VERSION 5.8 ;
BUSBITCHARS "[]" ;
DIVIDERCHAR "/" ;
UNITS
    DATABASE MICRONS 1000 ;
END UNITS

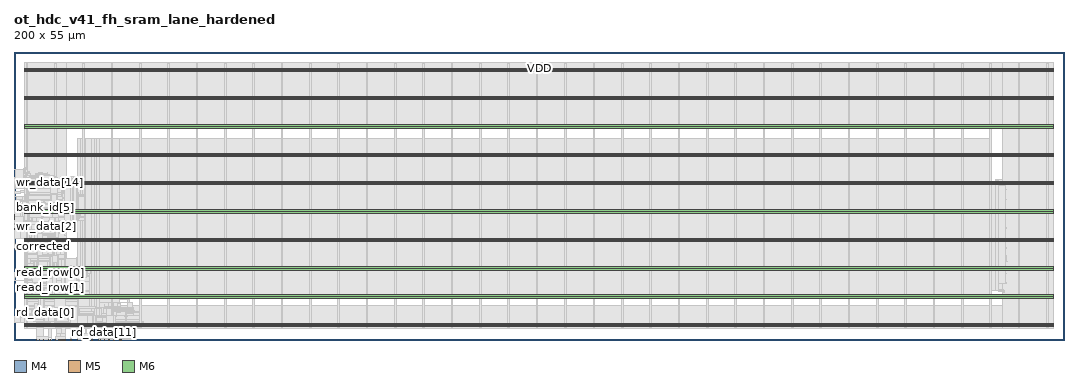
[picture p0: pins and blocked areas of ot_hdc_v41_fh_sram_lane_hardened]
MACRO ot_hdc_v41_fh_sram_lane_hardened
  FOREIGN ot_hdc_v41_fh_sram_lane_hardened 0 0 ;
  CLASS BLOCK ;
  SIZE 200 BY 55 ;
  PIN bank_id[0]
    DIRECTION INPUT ;
    USE SIGNAL ;
    PORT
      LAYER M4 ;
        RECT  0 26.4 0.084 26.424 ;
    END
  END bank_id[0]
  PIN bank_id[1]
    DIRECTION INPUT ;
    USE SIGNAL ;
    PORT
      LAYER M4 ;
        RECT  0 22.368 0.084 22.392 ;
    END
  END bank_id[1]
  PIN bank_id[2]
    DIRECTION INPUT ;
    USE SIGNAL ;
    PORT
      LAYER M4 ;
        RECT  0 22.176 0.084 22.2 ;
    END
  END bank_id[2]
  PIN bank_id[3]
    DIRECTION INPUT ;
    USE SIGNAL ;
    PORT
      LAYER M4 ;
        RECT  0 22.944 0.084 22.968 ;
    END
  END bank_id[3]
  PIN bank_id[4]
    DIRECTION INPUT ;
    USE SIGNAL ;
    PORT
      LAYER M4 ;
        RECT  0 23.616 0.084 23.64 ;
    END
  END bank_id[4]
  PIN bank_id[5]
    DIRECTION INPUT ;
    USE SIGNAL ;
    PORT
      LAYER M4 ;
        RECT  0 25.248 0.084 25.272 ;
    END
  END bank_id[5]
  PIN clk
    DIRECTION INPUT ;
    USE SIGNAL ;
    PORT
      LAYER M4 ;
        RECT  0 30.528 0.084 30.552 ;
    END
  END clk
  PIN corrected
    DIRECTION OUTPUT ;
    USE SIGNAL ;
    PORT
      LAYER M4 ;
        RECT  0 19.392 0.084 19.416 ;
    END
  END corrected
  PIN poisoned
    DIRECTION OUTPUT ;
    USE SIGNAL ;
    PORT
      LAYER M4 ;
        RECT  0 19.584 0.084 19.608 ;
    END
  END poisoned
  PIN rd_data[0]
    DIRECTION OUTPUT ;
    USE SIGNAL ;
    PORT
      LAYER M4 ;
        RECT  0 3.744 0.084 3.768 ;
    END
  END rd_data[0]
  PIN rd_data[10]
    DIRECTION OUTPUT ;
    USE SIGNAL ;
    PORT
      LAYER M5 ;
        RECT  4.8 0 4.824 0.084 ;
    END
  END rd_data[10]
  PIN rd_data[11]
    DIRECTION OUTPUT ;
    USE SIGNAL ;
    PORT
      LAYER M5 ;
        RECT  17.184 0 17.208 0.084 ;
    END
  END rd_data[11]
  PIN rd_data[12]
    DIRECTION OUTPUT ;
    USE SIGNAL ;
    PORT
      LAYER M5 ;
        RECT  18.24 0 18.264 0.084 ;
    END
  END rd_data[12]
  PIN rd_data[13]
    DIRECTION OUTPUT ;
    USE SIGNAL ;
    PORT
      LAYER M5 ;
        RECT  17.952 0 17.976 0.084 ;
    END
  END rd_data[13]
  PIN rd_data[14]
    DIRECTION OUTPUT ;
    USE SIGNAL ;
    PORT
      LAYER M5 ;
        RECT  18.912 0 18.936 0.084 ;
    END
  END rd_data[14]
  PIN rd_data[15]
    DIRECTION OUTPUT ;
    USE SIGNAL ;
    PORT
      LAYER M5 ;
        RECT  20.256 0 20.28 0.084 ;
    END
  END rd_data[15]
  PIN rd_data[16]
    DIRECTION OUTPUT ;
    USE SIGNAL ;
    PORT
      LAYER M5 ;
        RECT  20.16 0 20.184 0.084 ;
    END
  END rd_data[16]
  PIN rd_data[17]
    DIRECTION OUTPUT ;
    USE SIGNAL ;
    PORT
      LAYER M5 ;
        RECT  20.352 0 20.376 0.084 ;
    END
  END rd_data[17]
  PIN rd_data[18]
    DIRECTION OUTPUT ;
    USE SIGNAL ;
    PORT
      LAYER M5 ;
        RECT  20.448 0 20.472 0.084 ;
    END
  END rd_data[18]
  PIN rd_data[19]
    DIRECTION OUTPUT ;
    USE SIGNAL ;
    PORT
      LAYER M5 ;
        RECT  20.064 0 20.088 0.084 ;
    END
  END rd_data[19]
  PIN rd_data[1]
    DIRECTION OUTPUT ;
    USE SIGNAL ;
    PORT
      LAYER M5 ;
        RECT  4.32 0 4.344 0.084 ;
    END
  END rd_data[1]
  PIN rd_data[20]
    DIRECTION OUTPUT ;
    USE SIGNAL ;
    PORT
      LAYER M5 ;
        RECT  19.104 0 19.128 0.084 ;
    END
  END rd_data[20]
  PIN rd_data[21]
    DIRECTION OUTPUT ;
    USE SIGNAL ;
    PORT
      LAYER M5 ;
        RECT  16.512 0 16.536 0.084 ;
    END
  END rd_data[21]
  PIN rd_data[22]
    DIRECTION OUTPUT ;
    USE SIGNAL ;
    PORT
      LAYER M5 ;
        RECT  16.032 0 16.056 0.084 ;
    END
  END rd_data[22]
  PIN rd_data[23]
    DIRECTION OUTPUT ;
    USE SIGNAL ;
    PORT
      LAYER M5 ;
        RECT  13.824 0 13.848 0.084 ;
    END
  END rd_data[23]
  PIN rd_data[24]
    DIRECTION OUTPUT ;
    USE SIGNAL ;
    PORT
      LAYER M5 ;
        RECT  12.864 0 12.888 0.084 ;
    END
  END rd_data[24]
  PIN rd_data[25]
    DIRECTION OUTPUT ;
    USE SIGNAL ;
    PORT
      LAYER M5 ;
        RECT  14.976 0 15 0.084 ;
    END
  END rd_data[25]
  PIN rd_data[26]
    DIRECTION OUTPUT ;
    USE SIGNAL ;
    PORT
      LAYER M5 ;
        RECT  12 0 12.024 0.084 ;
    END
  END rd_data[26]
  PIN rd_data[27]
    DIRECTION OUTPUT ;
    USE SIGNAL ;
    PORT
      LAYER M5 ;
        RECT  14.688 0 14.712 0.084 ;
    END
  END rd_data[27]
  PIN rd_data[28]
    DIRECTION OUTPUT ;
    USE SIGNAL ;
    PORT
      LAYER M5 ;
        RECT  13.152 0 13.176 0.084 ;
    END
  END rd_data[28]
  PIN rd_data[29]
    DIRECTION OUTPUT ;
    USE SIGNAL ;
    PORT
      LAYER M5 ;
        RECT  10.752 0 10.776 0.084 ;
    END
  END rd_data[29]
  PIN rd_data[2]
    DIRECTION OUTPUT ;
    USE SIGNAL ;
    PORT
      LAYER M4 ;
        RECT  0 3.264 0.084 3.288 ;
    END
  END rd_data[2]
  PIN rd_data[30]
    DIRECTION OUTPUT ;
    USE SIGNAL ;
    PORT
      LAYER M5 ;
        RECT  10.944 0 10.968 0.084 ;
    END
  END rd_data[30]
  PIN rd_data[31]
    DIRECTION OUTPUT ;
    USE SIGNAL ;
    PORT
      LAYER M4 ;
        RECT  0 4.416 0.084 4.44 ;
    END
  END rd_data[31]
  PIN rd_data[3]
    DIRECTION OUTPUT ;
    USE SIGNAL ;
    PORT
      LAYER M5 ;
        RECT  6.912 0 6.936 0.084 ;
    END
  END rd_data[3]
  PIN rd_data[4]
    DIRECTION OUTPUT ;
    USE SIGNAL ;
    PORT
      LAYER M5 ;
        RECT  8.544 0 8.568 0.084 ;
    END
  END rd_data[4]
  PIN rd_data[5]
    DIRECTION OUTPUT ;
    USE SIGNAL ;
    PORT
      LAYER M5 ;
        RECT  7.968 0 7.992 0.084 ;
    END
  END rd_data[5]
  PIN rd_data[6]
    DIRECTION OUTPUT ;
    USE SIGNAL ;
    PORT
      LAYER M5 ;
        RECT  9.696 0 9.72 0.084 ;
    END
  END rd_data[6]
  PIN rd_data[7]
    DIRECTION OUTPUT ;
    USE SIGNAL ;
    PORT
      LAYER M5 ;
        RECT  9.024 0 9.048 0.084 ;
    END
  END rd_data[7]
  PIN rd_data[8]
    DIRECTION OUTPUT ;
    USE SIGNAL ;
    PORT
      LAYER M5 ;
        RECT  5.664 0 5.688 0.084 ;
    END
  END rd_data[8]
  PIN rd_data[9]
    DIRECTION OUTPUT ;
    USE SIGNAL ;
    PORT
      LAYER M5 ;
        RECT  6.528 0 6.552 0.084 ;
    END
  END rd_data[9]
  PIN rd_valid
    DIRECTION OUTPUT ;
    USE SIGNAL ;
    PORT
      LAYER M4 ;
        RECT  0 19.872 0.084 19.896 ;
    END
  END rd_valid
  PIN read_ok
    DIRECTION INPUT ;
    USE SIGNAL ;
    PORT
      LAYER M5 ;
        RECT  8.736 0 8.76 0.084 ;
    END
  END read_ok
  PIN read_row[0]
    DIRECTION INPUT ;
    USE SIGNAL ;
    PORT
      LAYER M4 ;
        RECT  0 12.768 0.084 12.792 ;
    END
  END read_row[0]
  PIN read_row[1]
    DIRECTION INPUT ;
    USE SIGNAL ;
    PORT
      LAYER M4 ;
        RECT  0 11.52 0.084 11.544 ;
    END
  END read_row[1]
  PIN read_row[2]
    DIRECTION INPUT ;
    USE SIGNAL ;
    PORT
      LAYER M5 ;
        RECT  9.216 0 9.24 0.084 ;
    END
  END read_row[2]
  PIN read_row[3]
    DIRECTION INPUT ;
    USE SIGNAL ;
    PORT
      LAYER M5 ;
        RECT  9.312 0 9.336 0.084 ;
    END
  END read_row[3]
  PIN read_row[4]
    DIRECTION INPUT ;
    USE SIGNAL ;
    PORT
      LAYER M5 ;
        RECT  8.928 0 8.952 0.084 ;
    END
  END read_row[4]
  PIN read_row[5]
    DIRECTION INPUT ;
    USE SIGNAL ;
    PORT
      LAYER M5 ;
        RECT  8.64 0 8.664 0.084 ;
    END
  END read_row[5]
  PIN read_row[6]
    DIRECTION INPUT ;
    USE SIGNAL ;
    PORT
      LAYER M5 ;
        RECT  9.12 0 9.144 0.084 ;
    END
  END read_row[6]
  PIN read_row[7]
    DIRECTION INPUT ;
    USE SIGNAL ;
    PORT
      LAYER M5 ;
        RECT  9.408 0 9.432 0.084 ;
    END
  END read_row[7]
  PIN read_row[8]
    DIRECTION INPUT ;
    USE SIGNAL ;
    PORT
      LAYER M5 ;
        RECT  9.504 0 9.528 0.084 ;
    END
  END read_row[8]
  PIN rst_n
    DIRECTION INPUT ;
    USE SIGNAL ;
    PORT
      LAYER M4 ;
        RECT  0 19.68 0.084 19.704 ;
    END
  END rst_n
  PIN wr_committed
    DIRECTION OUTPUT ;
    USE SIGNAL ;
    PORT
      LAYER M4 ;
        RECT  0 19.968 0.084 19.992 ;
    END
  END wr_committed
  PIN wr_data[0]
    DIRECTION INPUT ;
    USE SIGNAL ;
    PORT
      LAYER M4 ;
        RECT  0 24.384 0.084 24.408 ;
    END
  END wr_data[0]
  PIN wr_data[10]
    DIRECTION INPUT ;
    USE SIGNAL ;
    PORT
      LAYER M4 ;
        RECT  0 20.928 0.084 20.952 ;
    END
  END wr_data[10]
  PIN wr_data[11]
    DIRECTION INPUT ;
    USE SIGNAL ;
    PORT
      LAYER M4 ;
        RECT  0 28.8 0.084 28.824 ;
    END
  END wr_data[11]
  PIN wr_data[12]
    DIRECTION INPUT ;
    USE SIGNAL ;
    PORT
      LAYER M4 ;
        RECT  0 23.04 0.084 23.064 ;
    END
  END wr_data[12]
  PIN wr_data[13]
    DIRECTION INPUT ;
    USE SIGNAL ;
    PORT
      LAYER M4 ;
        RECT  0 23.232 0.084 23.256 ;
    END
  END wr_data[13]
  PIN wr_data[14]
    DIRECTION INPUT ;
    USE SIGNAL ;
    PORT
      LAYER M4 ;
        RECT  0 29.952 0.084 29.976 ;
    END
  END wr_data[14]
  PIN wr_data[15]
    DIRECTION INPUT ;
    USE SIGNAL ;
    PORT
      LAYER M4 ;
        RECT  0 30.624 0.084 30.648 ;
    END
  END wr_data[15]
  PIN wr_data[16]
    DIRECTION INPUT ;
    USE SIGNAL ;
    PORT
      LAYER M4 ;
        RECT  0 30.816 0.084 30.84 ;
    END
  END wr_data[16]
  PIN wr_data[17]
    DIRECTION INPUT ;
    USE SIGNAL ;
    PORT
      LAYER M4 ;
        RECT  0 29.376 0.084 29.4 ;
    END
  END wr_data[17]
  PIN wr_data[18]
    DIRECTION INPUT ;
    USE SIGNAL ;
    PORT
      LAYER M4 ;
        RECT  0 30.912 0.084 30.936 ;
    END
  END wr_data[18]
  PIN wr_data[19]
    DIRECTION INPUT ;
    USE SIGNAL ;
    PORT
      LAYER M4 ;
        RECT  0 30.72 0.084 30.744 ;
    END
  END wr_data[19]
  PIN wr_data[1]
    DIRECTION INPUT ;
    USE SIGNAL ;
    PORT
      LAYER M4 ;
        RECT  0 20.832 0.084 20.856 ;
    END
  END wr_data[1]
  PIN wr_data[20]
    DIRECTION INPUT ;
    USE SIGNAL ;
    PORT
      LAYER M4 ;
        RECT  0 31.008 0.084 31.032 ;
    END
  END wr_data[20]
  PIN wr_data[21]
    DIRECTION INPUT ;
    USE SIGNAL ;
    PORT
      LAYER M4 ;
        RECT  0 29.856 0.084 29.88 ;
    END
  END wr_data[21]
  PIN wr_data[22]
    DIRECTION INPUT ;
    USE SIGNAL ;
    PORT
      LAYER M4 ;
        RECT  0 30.048 0.084 30.072 ;
    END
  END wr_data[22]
  PIN wr_data[23]
    DIRECTION INPUT ;
    USE SIGNAL ;
    PORT
      LAYER M4 ;
        RECT  0 29.76 0.084 29.784 ;
    END
  END wr_data[23]
  PIN wr_data[24]
    DIRECTION INPUT ;
    USE SIGNAL ;
    PORT
      LAYER M4 ;
        RECT  0 27.936 0.084 27.96 ;
    END
  END wr_data[24]
  PIN wr_data[25]
    DIRECTION INPUT ;
    USE SIGNAL ;
    PORT
      LAYER M4 ;
        RECT  0 26.208 0.084 26.232 ;
    END
  END wr_data[25]
  PIN wr_data[26]
    DIRECTION INPUT ;
    USE SIGNAL ;
    PORT
      LAYER M4 ;
        RECT  0 24.576 0.084 24.6 ;
    END
  END wr_data[26]
  PIN wr_data[27]
    DIRECTION INPUT ;
    USE SIGNAL ;
    PORT
      LAYER M4 ;
        RECT  0 29.472 0.084 29.496 ;
    END
  END wr_data[27]
  PIN wr_data[28]
    DIRECTION INPUT ;
    USE SIGNAL ;
    PORT
      LAYER M4 ;
        RECT  0 23.136 0.084 23.16 ;
    END
  END wr_data[28]
  PIN wr_data[29]
    DIRECTION INPUT ;
    USE SIGNAL ;
    PORT
      LAYER M4 ;
        RECT  0 24.768 0.084 24.792 ;
    END
  END wr_data[29]
  PIN wr_data[2]
    DIRECTION INPUT ;
    USE SIGNAL ;
    PORT
      LAYER M4 ;
        RECT  0 21.6 0.084 21.624 ;
    END
  END wr_data[2]
  PIN wr_data[30]
    DIRECTION INPUT ;
    USE SIGNAL ;
    PORT
      LAYER M4 ;
        RECT  0 26.592 0.084 26.616 ;
    END
  END wr_data[30]
  PIN wr_data[31]
    DIRECTION INPUT ;
    USE SIGNAL ;
    PORT
      LAYER M4 ;
        RECT  0 28.32 0.084 28.344 ;
    END
  END wr_data[31]
  PIN wr_data[3]
    DIRECTION INPUT ;
    USE SIGNAL ;
    PORT
      LAYER M4 ;
        RECT  0 23.808 0.084 23.832 ;
    END
  END wr_data[3]
  PIN wr_data[4]
    DIRECTION INPUT ;
    USE SIGNAL ;
    PORT
      LAYER M4 ;
        RECT  0 20.448 0.084 20.472 ;
    END
  END wr_data[4]
  PIN wr_data[5]
    DIRECTION INPUT ;
    USE SIGNAL ;
    PORT
      LAYER M4 ;
        RECT  0 20.16 0.084 20.184 ;
    END
  END wr_data[5]
  PIN wr_data[6]
    DIRECTION INPUT ;
    USE SIGNAL ;
    PORT
      LAYER M4 ;
        RECT  0 20.736 0.084 20.76 ;
    END
  END wr_data[6]
  PIN wr_data[7]
    DIRECTION INPUT ;
    USE SIGNAL ;
    PORT
      LAYER M4 ;
        RECT  0 20.256 0.084 20.28 ;
    END
  END wr_data[7]
  PIN wr_data[8]
    DIRECTION INPUT ;
    USE SIGNAL ;
    PORT
      LAYER M4 ;
        RECT  0 20.064 0.084 20.088 ;
    END
  END wr_data[8]
  PIN wr_data[9]
    DIRECTION INPUT ;
    USE SIGNAL ;
    PORT
      LAYER M4 ;
        RECT  0 20.544 0.084 20.568 ;
    END
  END wr_data[9]
  PIN write_ok
    DIRECTION INPUT ;
    USE SIGNAL ;
    PORT
      LAYER M4 ;
        RECT  0 19.776 0.084 19.8 ;
    END
  END write_ok
  PIN write_row[0]
    DIRECTION INPUT ;
    USE SIGNAL ;
    PORT
      LAYER M4 ;
        RECT  0 23.712 0.084 23.736 ;
    END
  END write_row[0]
  PIN write_row[1]
    DIRECTION INPUT ;
    USE SIGNAL ;
    PORT
      LAYER M4 ;
        RECT  0 24.192 0.084 24.216 ;
    END
  END write_row[1]
  PIN write_row[2]
    DIRECTION INPUT ;
    USE SIGNAL ;
    PORT
      LAYER M4 ;
        RECT  0 27.36 0.084 27.384 ;
    END
  END write_row[2]
  PIN write_row[3]
    DIRECTION INPUT ;
    USE SIGNAL ;
    PORT
      LAYER M4 ;
        RECT  0 21.12 0.084 21.144 ;
    END
  END write_row[3]
  PIN write_row[4]
    DIRECTION INPUT ;
    USE SIGNAL ;
    PORT
      LAYER M4 ;
        RECT  0 20.64 0.084 20.664 ;
    END
  END write_row[4]
  PIN write_row[5]
    DIRECTION INPUT ;
    USE SIGNAL ;
    PORT
      LAYER M4 ;
        RECT  0 22.08 0.084 22.104 ;
    END
  END write_row[5]
  PIN write_row[6]
    DIRECTION INPUT ;
    USE SIGNAL ;
    PORT
      LAYER M4 ;
        RECT  0 22.56 0.084 22.584 ;
    END
  END write_row[6]
  PIN write_row[7]
    DIRECTION INPUT ;
    USE SIGNAL ;
    PORT
      LAYER M4 ;
        RECT  0 25.824 0.084 25.848 ;
    END
  END write_row[7]
  PIN write_row[8]
    DIRECTION INPUT ;
    USE SIGNAL ;
    PORT
      LAYER M4 ;
        RECT  0 25.152 0.084 25.176 ;
    END
  END write_row[8]
  PIN VDD
    DIRECTION INOUT ;
    USE POWER ;
    PORT
      LAYER M6 ;
        RECT  2.052 51.513 197.964 51.801 ;
        RECT  2.052 46.113 197.964 46.401 ;
        RECT  2.052 40.713 197.964 41.001 ;
        RECT  2.052 35.313 197.964 35.601 ;
        RECT  2.052 29.913 197.964 30.201 ;
        RECT  2.052 24.513 197.964 24.801 ;
        RECT  2.052 19.113 197.964 19.401 ;
        RECT  2.052 13.713 197.964 14.001 ;
        RECT  2.052 8.313 197.964 8.601 ;
        RECT  2.052 2.913 197.964 3.201 ;
    END
  END VDD
  PIN VSS
    DIRECTION INOUT ;
    USE GROUND ;
    PORT
      LAYER M6 ;
        RECT  2.052 51.129 197.964 51.417 ;
        RECT  2.052 45.729 197.964 46.017 ;
        RECT  2.052 40.329 197.964 40.617 ;
        RECT  2.052 34.929 197.964 35.217 ;
        RECT  2.052 29.529 197.964 29.817 ;
        RECT  2.052 24.129 197.964 24.417 ;
        RECT  2.052 18.729 197.964 19.017 ;
        RECT  2.052 13.329 197.964 13.617 ;
        RECT  2.052 7.929 197.964 8.217 ;
        RECT  2.052 2.529 197.964 2.817 ;
    END
  END VSS
  OBS
    LAYER RVTN ;
     RECT  2.052 2.16 197.964 2.295 ;
     RECT  2.052 2.565 197.964 2.835 ;
     RECT  2.052 3.105 197.964 3.375 ;
     RECT  2.052 3.645 197.964 3.915 ;
     RECT  2.052 4.185 197.964 4.455 ;
     RECT  2.052 4.725 197.964 4.995 ;
     RECT  2.052 5.265 197.964 5.535 ;
     RECT  2.052 5.805 197.964 6.075 ;
     RECT  2.052 6.345 197.964 6.48 ;
     RECT  2.052 6.48 10.044 6.615 ;
     RECT  188.244 6.48 197.964 6.615 ;
     RECT  2.052 6.885 10.044 7.155 ;
     RECT  188.244 6.885 197.964 7.155 ;
     RECT  2.052 7.425 10.044 7.695 ;
     RECT  188.244 7.425 197.964 7.695 ;
     RECT  2.052 7.965 10.044 8.235 ;
     RECT  188.244 7.965 197.964 8.235 ;
     RECT  2.052 8.505 10.044 8.775 ;
     RECT  188.244 8.505 197.964 8.775 ;
     RECT  2.052 9.045 10.044 9.315 ;
     RECT  188.244 9.045 197.964 9.315 ;
     RECT  2.052 9.585 10.044 9.855 ;
     RECT  188.244 9.585 197.964 9.855 ;
     RECT  2.052 10.125 10.044 10.395 ;
     RECT  188.244 10.125 197.964 10.395 ;
     RECT  2.052 10.665 10.044 10.935 ;
     RECT  188.244 10.665 197.964 10.935 ;
     RECT  2.052 11.205 10.044 11.475 ;
     RECT  188.244 11.205 197.964 11.475 ;
     RECT  2.052 11.745 10.044 12.015 ;
     RECT  188.244 11.745 197.964 12.015 ;
     RECT  2.052 12.285 10.044 12.555 ;
     RECT  188.244 12.285 197.964 12.555 ;
     RECT  2.052 12.825 10.044 13.095 ;
     RECT  188.244 12.825 197.964 13.095 ;
     RECT  2.052 13.365 10.044 13.635 ;
     RECT  188.244 13.365 197.964 13.635 ;
     RECT  2.052 13.905 10.044 14.175 ;
     RECT  188.244 13.905 197.964 14.175 ;
     RECT  2.052 14.445 10.044 14.715 ;
     RECT  188.244 14.445 197.964 14.715 ;
     RECT  2.052 14.985 10.044 15.255 ;
     RECT  188.244 14.985 197.964 15.255 ;
     RECT  2.052 15.525 10.044 15.795 ;
     RECT  188.244 15.525 197.964 15.795 ;
     RECT  2.052 16.065 10.044 16.335 ;
     RECT  188.244 16.065 197.964 16.335 ;
     RECT  2.052 16.605 10.044 16.875 ;
     RECT  188.244 16.605 197.964 16.875 ;
     RECT  2.052 17.145 10.044 17.415 ;
     RECT  188.244 17.145 197.964 17.415 ;
     RECT  2.052 17.685 10.044 17.955 ;
     RECT  188.244 17.685 197.964 17.955 ;
     RECT  2.052 18.225 10.044 18.495 ;
     RECT  188.244 18.225 197.964 18.495 ;
     RECT  2.052 18.765 10.044 19.035 ;
     RECT  188.244 18.765 197.964 19.035 ;
     RECT  2.052 19.305 10.044 19.575 ;
     RECT  188.244 19.305 197.964 19.575 ;
     RECT  2.052 19.845 10.044 20.115 ;
     RECT  188.244 19.845 197.964 20.115 ;
     RECT  2.052 20.385 10.044 20.655 ;
     RECT  188.244 20.385 197.964 20.655 ;
     RECT  2.052 20.925 10.044 21.195 ;
     RECT  188.244 20.925 197.964 21.195 ;
     RECT  2.052 21.465 10.044 21.735 ;
     RECT  188.244 21.465 197.964 21.735 ;
     RECT  2.052 22.005 10.044 22.275 ;
     RECT  188.244 22.005 197.964 22.275 ;
     RECT  2.052 22.545 10.044 22.815 ;
     RECT  188.244 22.545 197.964 22.815 ;
     RECT  2.052 23.085 10.044 23.355 ;
     RECT  188.244 23.085 197.964 23.355 ;
     RECT  2.052 23.625 10.044 23.895 ;
     RECT  188.244 23.625 197.964 23.895 ;
     RECT  2.052 24.165 10.044 24.435 ;
     RECT  188.244 24.165 197.964 24.435 ;
     RECT  2.052 24.705 10.044 24.975 ;
     RECT  188.244 24.705 197.964 24.975 ;
     RECT  2.052 25.245 10.044 25.515 ;
     RECT  188.244 25.245 197.964 25.515 ;
     RECT  2.052 25.785 10.044 26.055 ;
     RECT  188.244 25.785 197.964 26.055 ;
     RECT  2.052 26.325 10.044 26.595 ;
     RECT  188.244 26.325 197.964 26.595 ;
     RECT  2.052 26.865 10.044 27.135 ;
     RECT  188.244 26.865 197.964 27.135 ;
     RECT  2.052 27.405 10.044 27.675 ;
     RECT  188.244 27.405 197.964 27.675 ;
     RECT  2.052 27.945 10.044 28.215 ;
     RECT  188.244 27.945 197.964 28.215 ;
     RECT  2.052 28.485 10.044 28.755 ;
     RECT  188.244 28.485 197.964 28.755 ;
     RECT  2.052 29.025 10.044 29.295 ;
     RECT  188.244 29.025 197.964 29.295 ;
     RECT  2.052 29.565 10.044 29.835 ;
     RECT  188.244 29.565 197.964 29.835 ;
     RECT  2.052 30.105 10.044 30.375 ;
     RECT  188.244 30.105 197.964 30.375 ;
     RECT  2.052 30.645 10.044 30.915 ;
     RECT  188.244 30.645 197.964 30.915 ;
     RECT  2.052 31.185 10.044 31.455 ;
     RECT  188.244 31.185 197.964 31.455 ;
     RECT  2.052 31.725 10.044 31.995 ;
     RECT  188.244 31.725 197.964 31.995 ;
     RECT  2.052 32.265 10.044 32.535 ;
     RECT  188.244 32.265 197.964 32.535 ;
     RECT  2.052 32.805 10.044 33.075 ;
     RECT  188.244 32.805 197.964 33.075 ;
     RECT  2.052 33.345 10.044 33.615 ;
     RECT  188.244 33.345 197.964 33.615 ;
     RECT  2.052 33.885 10.044 34.155 ;
     RECT  188.244 33.885 197.964 34.155 ;
     RECT  2.052 34.425 10.044 34.695 ;
     RECT  188.244 34.425 197.964 34.695 ;
     RECT  2.052 34.965 10.044 35.235 ;
     RECT  188.244 34.965 197.964 35.235 ;
     RECT  2.052 35.505 10.044 35.775 ;
     RECT  188.244 35.505 197.964 35.775 ;
     RECT  2.052 36.045 10.044 36.315 ;
     RECT  188.244 36.045 197.964 36.315 ;
     RECT  2.052 36.585 10.044 36.855 ;
     RECT  188.244 36.585 197.964 36.855 ;
     RECT  2.052 37.125 10.044 37.395 ;
     RECT  188.244 37.125 197.964 37.395 ;
     RECT  2.052 37.665 10.044 37.935 ;
     RECT  188.244 37.665 197.964 37.935 ;
     RECT  2.052 38.205 10.044 38.475 ;
     RECT  188.244 38.205 197.964 38.475 ;
     RECT  2.052 38.745 10.044 39.015 ;
     RECT  188.244 38.745 197.964 39.015 ;
     RECT  2.052 39.285 10.044 39.555 ;
     RECT  188.244 39.285 197.964 39.555 ;
     RECT  2.052 39.825 10.044 40.095 ;
     RECT  188.244 39.825 197.964 40.095 ;
     RECT  2.052 40.365 10.044 40.5 ;
     RECT  188.244 40.365 197.964 40.5 ;
     RECT  2.052 40.5 197.964 40.635 ;
     RECT  2.052 40.905 197.964 41.175 ;
     RECT  2.052 41.445 197.964 41.715 ;
     RECT  2.052 41.985 197.964 42.255 ;
     RECT  2.052 42.525 197.964 42.795 ;
     RECT  2.052 43.065 197.964 43.335 ;
     RECT  2.052 43.605 197.964 43.875 ;
     RECT  2.052 44.145 197.964 44.415 ;
     RECT  2.052 44.685 197.964 44.955 ;
     RECT  2.052 45.225 197.964 45.495 ;
     RECT  2.052 45.765 197.964 46.035 ;
     RECT  2.052 46.305 197.964 46.575 ;
     RECT  2.052 46.845 197.964 47.115 ;
     RECT  2.052 47.385 197.964 47.655 ;
     RECT  2.052 47.925 197.964 48.195 ;
     RECT  2.052 48.465 197.964 48.735 ;
     RECT  2.052 49.005 197.964 49.275 ;
     RECT  2.052 49.545 197.964 49.815 ;
     RECT  2.052 50.085 197.964 50.355 ;
     RECT  2.052 50.625 197.964 50.895 ;
     RECT  2.052 51.165 197.964 51.435 ;
     RECT  2.052 51.705 197.964 51.975 ;
     RECT  2.052 52.245 197.964 52.515 ;
     RECT  2.052 52.785 197.964 52.92 ;
    LAYER RVTP ;
     RECT  2.052 2.295 197.964 2.565 ;
     RECT  2.052 2.835 197.964 3.105 ;
     RECT  2.052 3.375 197.964 3.645 ;
     RECT  2.052 3.915 197.964 4.185 ;
     RECT  2.052 4.455 197.964 4.725 ;
     RECT  2.052 4.995 197.964 5.265 ;
     RECT  2.052 5.535 197.964 5.805 ;
     RECT  2.052 6.075 197.964 6.345 ;
     RECT  2.052 6.615 10.044 6.885 ;
     RECT  188.244 6.615 197.964 6.885 ;
     RECT  2.052 7.155 10.044 7.425 ;
     RECT  188.244 7.155 197.964 7.425 ;
     RECT  2.052 7.695 10.044 7.965 ;
     RECT  188.244 7.695 197.964 7.965 ;
     RECT  2.052 8.235 10.044 8.505 ;
     RECT  188.244 8.235 197.964 8.505 ;
     RECT  2.052 8.775 10.044 9.045 ;
     RECT  188.244 8.775 197.964 9.045 ;
     RECT  2.052 9.315 10.044 9.585 ;
     RECT  188.244 9.315 197.964 9.585 ;
     RECT  2.052 9.855 10.044 10.125 ;
     RECT  188.244 9.855 197.964 10.125 ;
     RECT  2.052 10.395 10.044 10.665 ;
     RECT  188.244 10.395 197.964 10.665 ;
     RECT  2.052 10.935 10.044 11.205 ;
     RECT  188.244 10.935 197.964 11.205 ;
     RECT  2.052 11.475 10.044 11.745 ;
     RECT  188.244 11.475 197.964 11.745 ;
     RECT  2.052 12.015 10.044 12.285 ;
     RECT  188.244 12.015 197.964 12.285 ;
     RECT  2.052 12.555 10.044 12.825 ;
     RECT  188.244 12.555 197.964 12.825 ;
     RECT  2.052 13.095 10.044 13.365 ;
     RECT  188.244 13.095 197.964 13.365 ;
     RECT  2.052 13.635 10.044 13.905 ;
     RECT  188.244 13.635 197.964 13.905 ;
     RECT  2.052 14.175 10.044 14.445 ;
     RECT  188.244 14.175 197.964 14.445 ;
     RECT  2.052 14.715 10.044 14.985 ;
     RECT  188.244 14.715 197.964 14.985 ;
     RECT  2.052 15.255 10.044 15.525 ;
     RECT  188.244 15.255 197.964 15.525 ;
     RECT  2.052 15.795 10.044 16.065 ;
     RECT  188.244 15.795 197.964 16.065 ;
     RECT  2.052 16.335 10.044 16.605 ;
     RECT  188.244 16.335 197.964 16.605 ;
     RECT  2.052 16.875 10.044 17.145 ;
     RECT  188.244 16.875 197.964 17.145 ;
     RECT  2.052 17.415 10.044 17.685 ;
     RECT  188.244 17.415 197.964 17.685 ;
     RECT  2.052 17.955 10.044 18.225 ;
     RECT  188.244 17.955 197.964 18.225 ;
     RECT  2.052 18.495 10.044 18.765 ;
     RECT  188.244 18.495 197.964 18.765 ;
     RECT  2.052 19.035 10.044 19.305 ;
     RECT  188.244 19.035 197.964 19.305 ;
     RECT  2.052 19.575 10.044 19.845 ;
     RECT  188.244 19.575 197.964 19.845 ;
     RECT  2.052 20.115 10.044 20.385 ;
     RECT  188.244 20.115 197.964 20.385 ;
     RECT  2.052 20.655 10.044 20.925 ;
     RECT  188.244 20.655 197.964 20.925 ;
     RECT  2.052 21.195 10.044 21.465 ;
     RECT  188.244 21.195 197.964 21.465 ;
     RECT  2.052 21.735 10.044 22.005 ;
     RECT  188.244 21.735 197.964 22.005 ;
     RECT  2.052 22.275 10.044 22.545 ;
     RECT  188.244 22.275 197.964 22.545 ;
     RECT  2.052 22.815 10.044 23.085 ;
     RECT  188.244 22.815 197.964 23.085 ;
     RECT  2.052 23.355 10.044 23.625 ;
     RECT  188.244 23.355 197.964 23.625 ;
     RECT  2.052 23.895 10.044 24.165 ;
     RECT  188.244 23.895 197.964 24.165 ;
     RECT  2.052 24.435 10.044 24.705 ;
     RECT  188.244 24.435 197.964 24.705 ;
     RECT  2.052 24.975 10.044 25.245 ;
     RECT  188.244 24.975 197.964 25.245 ;
     RECT  2.052 25.515 10.044 25.785 ;
     RECT  188.244 25.515 197.964 25.785 ;
     RECT  2.052 26.055 10.044 26.325 ;
     RECT  188.244 26.055 197.964 26.325 ;
     RECT  2.052 26.595 10.044 26.865 ;
     RECT  188.244 26.595 197.964 26.865 ;
     RECT  2.052 27.135 10.044 27.405 ;
     RECT  188.244 27.135 197.964 27.405 ;
     RECT  2.052 27.675 10.044 27.945 ;
     RECT  188.244 27.675 197.964 27.945 ;
     RECT  2.052 28.215 10.044 28.485 ;
     RECT  188.244 28.215 197.964 28.485 ;
     RECT  2.052 28.755 10.044 29.025 ;
     RECT  188.244 28.755 197.964 29.025 ;
     RECT  2.052 29.295 10.044 29.565 ;
     RECT  188.244 29.295 197.964 29.565 ;
     RECT  2.052 29.835 10.044 30.105 ;
     RECT  188.244 29.835 197.964 30.105 ;
     RECT  2.052 30.375 10.044 30.645 ;
     RECT  188.244 30.375 197.964 30.645 ;
     RECT  2.052 30.915 10.044 31.185 ;
     RECT  188.244 30.915 197.964 31.185 ;
     RECT  2.052 31.455 10.044 31.725 ;
     RECT  188.244 31.455 197.964 31.725 ;
     RECT  2.052 31.995 10.044 32.265 ;
     RECT  188.244 31.995 197.964 32.265 ;
     RECT  2.052 32.535 10.044 32.805 ;
     RECT  188.244 32.535 197.964 32.805 ;
     RECT  2.052 33.075 10.044 33.345 ;
     RECT  188.244 33.075 197.964 33.345 ;
     RECT  2.052 33.615 10.044 33.885 ;
     RECT  188.244 33.615 197.964 33.885 ;
     RECT  2.052 34.155 10.044 34.425 ;
     RECT  188.244 34.155 197.964 34.425 ;
     RECT  2.052 34.695 10.044 34.965 ;
     RECT  188.244 34.695 197.964 34.965 ;
     RECT  2.052 35.235 10.044 35.505 ;
     RECT  188.244 35.235 197.964 35.505 ;
     RECT  2.052 35.775 10.044 36.045 ;
     RECT  188.244 35.775 197.964 36.045 ;
     RECT  2.052 36.315 10.044 36.585 ;
     RECT  188.244 36.315 197.964 36.585 ;
     RECT  2.052 36.855 10.044 37.125 ;
     RECT  188.244 36.855 197.964 37.125 ;
     RECT  2.052 37.395 10.044 37.665 ;
     RECT  188.244 37.395 197.964 37.665 ;
     RECT  2.052 37.935 10.044 38.205 ;
     RECT  188.244 37.935 197.964 38.205 ;
     RECT  2.052 38.475 10.044 38.745 ;
     RECT  188.244 38.475 197.964 38.745 ;
     RECT  2.052 39.015 10.044 39.285 ;
     RECT  188.244 39.015 197.964 39.285 ;
     RECT  2.052 39.555 10.044 39.825 ;
     RECT  188.244 39.555 197.964 39.825 ;
     RECT  2.052 40.095 10.044 40.365 ;
     RECT  188.244 40.095 197.964 40.365 ;
     RECT  2.052 40.635 197.964 40.905 ;
     RECT  2.052 41.175 197.964 41.445 ;
     RECT  2.052 41.715 197.964 41.985 ;
     RECT  2.052 42.255 197.964 42.525 ;
     RECT  2.052 42.795 197.964 43.065 ;
     RECT  2.052 43.335 197.964 43.605 ;
     RECT  2.052 43.875 197.964 44.145 ;
     RECT  2.052 44.415 197.964 44.685 ;
     RECT  2.052 44.955 197.964 45.225 ;
     RECT  2.052 45.495 197.964 45.765 ;
     RECT  2.052 46.035 197.964 46.305 ;
     RECT  2.052 46.575 197.964 46.845 ;
     RECT  2.052 47.115 197.964 47.385 ;
     RECT  2.052 47.655 197.964 47.925 ;
     RECT  2.052 48.195 197.964 48.465 ;
     RECT  2.052 48.735 197.964 49.005 ;
     RECT  2.052 49.275 197.964 49.545 ;
     RECT  2.052 49.815 197.964 50.085 ;
     RECT  2.052 50.355 197.964 50.625 ;
     RECT  2.052 50.895 197.964 51.165 ;
     RECT  2.052 51.435 197.964 51.705 ;
     RECT  2.052 51.975 197.964 52.245 ;
     RECT  2.052 52.515 197.964 52.785 ;
    LAYER M1 ;
     RECT  2.052 2.151 197.964 6.489 ;
     RECT  12.096 8.64 186.192 38.34 ;
     RECT  2.052 6.489 10.044 40.491 ;
     RECT  188.244 6.489 197.964 40.491 ;
     RECT  2.052 40.491 197.964 52.929 ;
    LAYER M2 ;
     RECT  0.103 27.342 0.571 27.36 ;
     RECT  0.103 22.05 1.147 22.068 ;
     RECT  0.571 23.598 1.147 23.994 ;
     RECT  0.571 25.722 1.147 25.74 ;
     RECT  1.147 20.322 1.687 26.01 ;
     RECT  0.571 26.802 1.687 27.36 ;
     RECT  0.571 30.582 1.759 30.6 ;
     RECT  0.571 31.392 1.759 31.41 ;
     RECT  1.147 3.276 2.052 4.374 ;
     RECT  0.103 11.25 2.052 11.268 ;
     RECT  0.103 12.222 2.052 12.24 ;
     RECT  1.687 19.62 2.052 27.36 ;
     RECT  1.147 28.152 2.052 28.44 ;
     RECT  1.147 29.502 2.052 29.52 ;
     RECT  1.759 30.582 2.052 31.41 ;
     RECT  1.723 32.202 2.052 32.22 ;
     RECT  2.052 2.151 10.044 52.929 ;
     RECT  10.044 22.014 10.247 31.14 ;
     RECT  10.044 8.586 10.283 10.116 ;
     RECT  10.044 11.556 10.283 15.282 ;
     RECT  10.247 23.166 10.283 31.14 ;
     RECT  10.283 8.586 10.679 9.27 ;
     RECT  10.283 11.556 10.823 15.21 ;
     RECT  10.283 25.956 10.823 31.14 ;
     RECT  10.823 26.226 10.859 31.14 ;
     RECT  10.283 10.098 10.931 10.116 ;
     RECT  10.044 2.151 10.975 7.758 ;
     RECT  10.859 26.226 11.327 27.666 ;
     RECT  10.859 29.736 11.327 31.14 ;
     RECT  11.327 26.226 11.363 27.504 ;
     RECT  10.679 8.586 11.435 8.604 ;
     RECT  10.975 2.106 11.795 7.758 ;
     RECT  10.823 11.754 12.096 15.21 ;
     RECT  10.247 22.014 12.096 22.032 ;
     RECT  10.283 23.166 12.096 25.038 ;
     RECT  11.363 26.226 12.096 26.586 ;
     RECT  11.363 27.486 12.096 27.504 ;
     RECT  10.859 28.422 12.096 28.944 ;
     RECT  11.327 29.88 12.096 31.14 ;
     RECT  11.795 2.151 13.991 7.758 ;
     RECT  13.991 2.151 16.051 7.722 ;
     RECT  16.051 2.106 17.987 7.722 ;
     RECT  17.987 2.151 18.931 7.722 ;
     RECT  18.931 2.106 19.643 7.722 ;
     RECT  19.643 2.106 20.003 6.912 ;
     RECT  20.003 2.151 20.219 6.912 ;
     RECT  19.643 7.668 21.587 7.722 ;
     RECT  21.587 7.668 22.019 7.686 ;
     RECT  12.096 8.64 186.192 38.34 ;
     RECT  186.979 9.522 187.015 17.91 ;
     RECT  186.979 18.666 187.015 18.684 ;
     RECT  187.015 9.522 187.411 18.684 ;
     RECT  186.979 19.512 187.411 24.804 ;
     RECT  187.411 9.522 187.447 24.804 ;
     RECT  186.979 25.56 187.447 30.6 ;
     RECT  20.219 2.151 188.244 6.489 ;
     RECT  187.447 9.216 188.244 30.6 ;
     RECT  10.044 40.491 188.244 52.929 ;
     RECT  188.244 2.151 197.964 52.929 ;
    LAYER M3 ;
     RECT  22.68 0.139 22.698 0.187 ;
     RECT  7.164 0.091 7.182 0.571 ;
     RECT  8.496 0.091 8.514 0.571 ;
     RECT  8.1 0.571 8.91 1.147 ;
     RECT  13.536 0.091 13.554 1.147 ;
     RECT  18.648 0.571 18.666 1.147 ;
     RECT  8.1 1.147 9.45 1.195 ;
     RECT  12.024 1.147 12.042 2.101 ;
     RECT  14.724 1.147 16.074 2.101 ;
     RECT  17.208 1.147 17.226 2.101 ;
     RECT  18.648 1.147 18.954 2.101 ;
     RECT  20.196 1.147 20.214 2.101 ;
     RECT  14.724 2.101 17.226 2.129 ;
     RECT  6.588 0.571 7.182 2.143 ;
     RECT  8.1 1.195 9.558 2.143 ;
     RECT  13.536 1.147 13.878 2.143 ;
     RECT  5.724 2.107 5.742 2.191 ;
     RECT  10.764 1.147 10.998 2.191 ;
     RECT  11.772 2.101 12.042 2.191 ;
     RECT  16.128 2.129 17.226 2.191 ;
     RECT  17.964 2.101 18.954 2.191 ;
     RECT  19.98 2.101 20.214 2.191 ;
     RECT  10.764 2.191 12.042 2.263 ;
     RECT  13.107 2.143 13.878 2.263 ;
     RECT  14.724 2.129 15.39 2.263 ;
     RECT  16.128 2.191 20.214 2.263 ;
     RECT  21.708 0.091 21.726 2.263 ;
     RECT  22.608 0.187 22.698 2.263 ;
     RECT  23.907 2.143 23.997 2.263 ;
     RECT  10.764 2.263 15.39 2.299 ;
     RECT  16.128 2.263 20.61 2.299 ;
     RECT  21.708 2.263 22.698 2.299 ;
     RECT  6.588 2.143 9.558 2.347 ;
     RECT  10.584 2.299 15.39 2.347 ;
     RECT  16.128 2.299 22.698 2.371 ;
     RECT  23.508 2.263 23.997 2.371 ;
     RECT  2.307 2.143 2.397 2.413 ;
     RECT  29.307 2.143 29.397 2.413 ;
     RECT  34.707 2.143 34.797 2.413 ;
     RECT  40.107 2.143 40.197 2.413 ;
     RECT  45.507 2.143 45.597 2.413 ;
     RECT  50.907 2.143 50.997 2.413 ;
     RECT  56.307 2.143 56.397 2.413 ;
     RECT  61.707 2.143 61.797 2.413 ;
     RECT  67.107 2.143 67.197 2.413 ;
     RECT  72.507 2.143 72.597 2.413 ;
     RECT  77.907 2.143 77.997 2.413 ;
     RECT  83.307 2.143 83.397 2.413 ;
     RECT  88.707 2.143 88.797 2.413 ;
     RECT  94.107 2.143 94.197 2.413 ;
     RECT  99.507 2.143 99.597 2.413 ;
     RECT  104.907 2.143 104.997 2.413 ;
     RECT  110.307 2.143 110.397 2.413 ;
     RECT  115.707 2.143 115.797 2.413 ;
     RECT  121.107 2.143 121.197 2.413 ;
     RECT  126.507 2.143 126.597 2.413 ;
     RECT  131.907 2.143 131.997 2.413 ;
     RECT  137.307 2.143 137.397 2.413 ;
     RECT  142.707 2.143 142.797 2.413 ;
     RECT  148.107 2.143 148.197 2.413 ;
     RECT  153.507 2.143 153.597 2.413 ;
     RECT  158.907 2.143 158.997 2.413 ;
     RECT  164.307 2.143 164.397 2.413 ;
     RECT  169.707 2.143 169.797 2.413 ;
     RECT  175.107 2.143 175.197 2.413 ;
     RECT  180.507 2.143 180.597 2.413 ;
     RECT  185.907 2.143 185.997 2.413 ;
     RECT  191.307 2.143 191.397 2.413 ;
     RECT  196.707 2.143 196.797 2.413 ;
     RECT  16.128 2.371 24.246 2.489 ;
     RECT  5.436 2.191 5.742 2.569 ;
     RECT  6.588 2.347 15.39 2.569 ;
     RECT  4.68 2.299 4.698 2.605 ;
     RECT  4.572 2.605 4.698 2.731 ;
     RECT  5.436 2.569 15.39 2.731 ;
     RECT  24.912 2.803 24.93 3.029 ;
     RECT  4.572 2.731 15.39 3.145 ;
     RECT  4.464 3.145 15.39 3.181 ;
     RECT  16.128 2.489 24.189 3.181 ;
     RECT  4.464 3.181 24.189 3.299 ;
     RECT  4.464 3.299 16.866 3.307 ;
     RECT  17.64 3.299 24.189 3.335 ;
     RECT  17.676 3.335 24.189 3.379 ;
     RECT  4.284 3.307 16.866 3.443 ;
     RECT  4.284 3.443 5.742 3.451 ;
     RECT  4.176 3.451 5.742 3.541 ;
     RECT  17.676 3.379 24.606 3.569 ;
     RECT  17.676 3.569 24.189 3.875 ;
     RECT  3.78 3.541 5.742 3.883 ;
     RECT  6.48 3.443 16.866 4.261 ;
     RECT  17.676 3.875 17.766 4.261 ;
     RECT  3.42 3.883 5.742 4.351 ;
     RECT  6.48 4.261 17.766 4.351 ;
     RECT  1.152 3.259 1.17 4.445 ;
     RECT  2.307 2.413 2.589 4.459 ;
     RECT  3.42 4.351 17.766 4.459 ;
     RECT  2.307 4.459 17.766 4.649 ;
     RECT  4.176 4.649 17.766 4.657 ;
     RECT  18.507 3.875 24.189 4.657 ;
     RECT  2.307 4.649 3.438 4.927 ;
     RECT  2.268 4.927 3.438 4.991 ;
     RECT  4.176 4.657 24.189 5.459 ;
     RECT  4.176 5.459 22.878 5.531 ;
     RECT  3.384 4.991 3.438 5.575 ;
     RECT  4.176 5.531 22.806 5.575 ;
     RECT  3.384 5.575 22.806 5.737 ;
     RECT  2.268 4.991 2.589 5.789 ;
     RECT  2.307 5.789 2.589 5.809 ;
     RECT  3.312 5.737 22.806 5.809 ;
     RECT  2.307 5.809 22.806 5.999 ;
     RECT  14.76 5.999 22.806 6.125 ;
     RECT  17.244 6.125 22.806 6.143 ;
     RECT  23.907 5.459 24.189 6.227 ;
     RECT  29.307 2.413 29.589 6.227 ;
     RECT  34.707 2.413 34.989 6.227 ;
     RECT  40.107 2.413 40.389 6.227 ;
     RECT  45.507 2.413 45.789 6.227 ;
     RECT  50.907 2.413 51.189 6.227 ;
     RECT  56.307 2.413 56.589 6.227 ;
     RECT  61.707 2.413 61.989 6.227 ;
     RECT  67.107 2.413 67.389 6.227 ;
     RECT  72.507 2.413 72.789 6.227 ;
     RECT  77.907 2.413 78.189 6.227 ;
     RECT  83.307 2.413 83.589 6.227 ;
     RECT  88.707 2.413 88.989 6.227 ;
     RECT  94.107 2.413 94.389 6.227 ;
     RECT  99.507 2.413 99.789 6.227 ;
     RECT  104.907 2.413 105.189 6.227 ;
     RECT  110.307 2.413 110.589 6.227 ;
     RECT  115.707 2.413 115.989 6.227 ;
     RECT  121.107 2.413 121.389 6.227 ;
     RECT  126.507 2.413 126.789 6.227 ;
     RECT  131.907 2.413 132.189 6.227 ;
     RECT  137.307 2.413 137.589 6.227 ;
     RECT  142.707 2.413 142.989 6.227 ;
     RECT  148.107 2.413 148.389 6.227 ;
     RECT  153.507 2.413 153.789 6.227 ;
     RECT  158.907 2.413 159.189 6.227 ;
     RECT  164.307 2.413 164.589 6.227 ;
     RECT  169.707 2.413 169.989 6.227 ;
     RECT  175.107 2.413 175.389 6.227 ;
     RECT  180.507 2.413 180.789 6.227 ;
     RECT  185.907 2.413 186.189 6.227 ;
     RECT  17.244 6.143 20.646 6.269 ;
     RECT  21.42 6.143 22.806 6.269 ;
     RECT  14.76 6.125 16.326 6.305 ;
     RECT  15.084 6.305 16.326 6.317 ;
     RECT  17.244 6.269 20.214 6.377 ;
     RECT  15.084 6.317 15.714 6.413 ;
     RECT  2.307 5.999 13.986 6.449 ;
     RECT  17.244 6.377 18.597 6.449 ;
     RECT  2.307 6.449 13.197 6.497 ;
     RECT  18.507 6.449 18.597 6.497 ;
     RECT  23.907 6.227 23.997 6.497 ;
     RECT  29.307 6.227 29.397 6.497 ;
     RECT  34.707 6.227 34.797 6.497 ;
     RECT  40.107 6.227 40.197 6.497 ;
     RECT  45.507 6.227 45.597 6.497 ;
     RECT  50.907 6.227 50.997 6.497 ;
     RECT  56.307 6.227 56.397 6.497 ;
     RECT  61.707 6.227 61.797 6.497 ;
     RECT  67.107 6.227 67.197 6.497 ;
     RECT  72.507 6.227 72.597 6.497 ;
     RECT  77.907 6.227 77.997 6.497 ;
     RECT  83.307 6.227 83.397 6.497 ;
     RECT  88.707 6.227 88.797 6.497 ;
     RECT  94.107 6.227 94.197 6.497 ;
     RECT  99.507 6.227 99.597 6.497 ;
     RECT  104.907 6.227 104.997 6.497 ;
     RECT  110.307 6.227 110.397 6.497 ;
     RECT  115.707 6.227 115.797 6.497 ;
     RECT  121.107 6.227 121.197 6.497 ;
     RECT  126.507 6.227 126.597 6.497 ;
     RECT  131.907 6.227 131.997 6.497 ;
     RECT  137.307 6.227 137.397 6.497 ;
     RECT  142.707 6.227 142.797 6.497 ;
     RECT  148.107 6.227 148.197 6.497 ;
     RECT  153.507 6.227 153.597 6.497 ;
     RECT  158.907 6.227 158.997 6.497 ;
     RECT  164.307 6.227 164.397 6.497 ;
     RECT  169.707 6.227 169.797 6.497 ;
     RECT  175.107 6.227 175.197 6.497 ;
     RECT  180.507 6.227 180.597 6.497 ;
     RECT  185.907 6.227 185.997 6.497 ;
     RECT  17.244 6.449 17.262 6.719 ;
     RECT  15.084 6.413 15.102 6.893 ;
     RECT  19.62 6.377 20.214 6.917 ;
     RECT  21.564 6.269 22.626 7.133 ;
     RECT  19.62 6.917 20.07 7.223 ;
     RECT  2.307 6.497 12.618 7.421 ;
     RECT  2.307 7.421 12.078 7.655 ;
     RECT  21.564 7.133 22.014 7.691 ;
     RECT  20.052 7.223 20.07 7.709 ;
     RECT  21.564 7.691 21.582 7.727 ;
     RECT  13.968 6.449 13.986 7.763 ;
     RECT  2.307 7.655 11.97 8.311 ;
     RECT  2.268 8.311 11.97 8.525 ;
     RECT  2.307 8.525 11.97 8.64 ;
     RECT  188.424 8.977 188.442 9.085 ;
     RECT  187.452 9.211 187.47 9.355 ;
     RECT  188.424 9.085 188.658 9.437 ;
     RECT  187.452 9.355 187.506 9.517 ;
     RECT  188.424 9.437 188.442 9.533 ;
     RECT  2.307 8.64 186.192 9.931 ;
     RECT  2.268 9.931 186.192 10.781 ;
     RECT  188.784 10.741 188.802 10.831 ;
     RECT  2.268 10.781 10.206 10.877 ;
     RECT  188.784 10.831 188.982 10.877 ;
     RECT  188.748 10.939 188.766 11.209 ;
     RECT  188.64 11.209 188.766 11.399 ;
     RECT  10.944 10.781 186.192 11.551 ;
     RECT  188.748 11.399 188.766 11.741 ;
     RECT  10.8 11.551 186.192 11.777 ;
     RECT  11.268 11.777 186.192 11.933 ;
     RECT  2.268 10.877 10.026 12.361 ;
     RECT  2.232 12.361 10.026 12.515 ;
     RECT  188.784 11.899 188.802 12.667 ;
     RECT  188.784 12.667 188.946 12.757 ;
     RECT  188.748 12.757 188.946 12.785 ;
     RECT  0.108 11.245 0.126 12.797 ;
     RECT  188.748 12.785 188.802 12.797 ;
     RECT  11.412 11.933 186.192 13.441 ;
     RECT  188.784 12.797 188.802 13.568 ;
     RECT  10.8 13.441 186.192 13.757 ;
     RECT  10.8 13.757 10.962 14.141 ;
     RECT  11.772 13.757 186.192 14.381 ;
     RECT  11.916 14.381 186.192 14.429 ;
     RECT  2.268 12.515 10.026 14.485 ;
     RECT  10.8 14.141 10.854 14.485 ;
     RECT  186.984 9.517 187.506 14.779 ;
     RECT  188.748 14.203 188.766 14.875 ;
     RECT  186.984 14.779 187.542 14.945 ;
     RECT  188.712 14.875 188.766 14.945 ;
     RECT  188.964 14.971 189.198 15.017 ;
     RECT  2.268 14.485 10.854 15.101 ;
     RECT  11.952 14.429 186.192 15.187 ;
     RECT  188.964 15.017 189.09 15.215 ;
     RECT  11.916 15.187 186.192 15.293 ;
     RECT  188.964 15.215 188.982 15.296 ;
     RECT  2.268 15.101 10.278 15.485 ;
     RECT  186.984 14.945 187.506 15.835 ;
     RECT  186.984 15.835 187.578 15.989 ;
     RECT  186.984 15.989 187.542 16.061 ;
     RECT  188.784 15.871 188.802 16.105 ;
     RECT  188.784 16.105 188.982 16.157 ;
     RECT  2.268 15.485 9.846 16.295 ;
     RECT  188.784 16.157 188.874 16.411 ;
     RECT  188.64 16.411 188.874 16.529 ;
     RECT  188.784 16.529 188.874 16.541 ;
     RECT  9.612 16.295 9.846 17.105 ;
     RECT  2.268 16.295 8.766 17.221 ;
     RECT  9.612 17.105 9.702 17.221 ;
     RECT  188.856 16.541 188.874 17.455 ;
     RECT  188.856 17.455 189.09 17.501 ;
     RECT  188.856 17.501 189.018 17.581 ;
     RECT  2.268 17.221 9.702 17.608 ;
     RECT  188.676 17.581 189.018 17.693 ;
     RECT  188.676 17.693 188.874 17.789 ;
     RECT  188.676 17.789 188.766 17.885 ;
     RECT  2.196 17.608 9.702 18.031 ;
     RECT  2.196 18.031 9.81 18.187 ;
     RECT  2.196 18.187 9.918 18.227 ;
     RECT  2.196 18.227 9.81 18.491 ;
     RECT  188.748 17.885 188.766 18.571 ;
     RECT  2.196 18.491 9.522 18.689 ;
     RECT  186.984 16.061 187.506 18.689 ;
     RECT  2.196 18.689 8.658 18.697 ;
     RECT  188.748 18.571 188.802 18.715 ;
     RECT  9.504 18.689 9.522 18.761 ;
     RECT  188.748 18.715 188.982 18.761 ;
     RECT  2.124 18.697 8.658 18.959 ;
     RECT  188.748 18.761 188.874 19.037 ;
     RECT  2.124 18.959 8.37 19.075 ;
     RECT  188.748 19.037 188.802 19.139 ;
     RECT  187.416 18.689 187.506 19.507 ;
     RECT  2.088 19.075 8.37 19.615 ;
     RECT  188.784 19.139 188.802 19.768 ;
     RECT  188.784 19.768 188.874 19.805 ;
     RECT  188.784 19.805 188.838 19.885 ;
     RECT  9.9 19.885 9.918 19.921 ;
     RECT  1.692 19.615 8.37 20.011 ;
     RECT  0.324 19.963 0.342 20.093 ;
     RECT  1.692 20.011 8.406 20.191 ;
     RECT  9.684 19.921 9.918 20.191 ;
     RECT  1.692 20.191 8.586 20.251 ;
     RECT  188.676 19.885 188.838 20.623 ;
     RECT  1.152 20.251 8.586 20.731 ;
     RECT  9.36 20.191 9.918 20.731 ;
     RECT  188.676 20.623 188.874 20.765 ;
     RECT  1.152 20.731 9.918 20.993 ;
     RECT  186.984 19.507 187.506 21.019 ;
     RECT  1.152 20.993 3.33 21.119 ;
     RECT  186.984 21.019 187.542 21.191 ;
     RECT  4.14 20.993 9.918 21.271 ;
     RECT  188.748 20.765 188.874 21.307 ;
     RECT  188.748 21.307 188.982 21.425 ;
     RECT  188.748 21.425 188.874 21.631 ;
     RECT  1.152 21.119 3.294 21.695 ;
     RECT  188.676 21.631 188.874 21.725 ;
     RECT  188.676 21.725 188.766 21.917 ;
     RECT  12.096 15.293 186.192 22.009 ;
     RECT  2.196 21.695 3.294 22.081 ;
     RECT  4.14 21.271 10.026 22.081 ;
     RECT  0.108 22.045 0.126 22.397 ;
     RECT  2.196 22.081 10.098 22.505 ;
     RECT  2.268 22.505 10.098 22.577 ;
     RECT  4.356 22.577 10.098 22.621 ;
     RECT  188.748 21.917 188.766 22.651 ;
     RECT  188.748 22.651 188.91 22.739 ;
     RECT  188.748 22.739 188.874 23.045 ;
     RECT  1.152 21.695 1.17 23.131 ;
     RECT  188.748 23.045 188.802 23.165 ;
     RECT  2.268 22.577 3.618 23.279 ;
     RECT  4.356 22.621 10.242 23.323 ;
     RECT  11.412 22.009 186.192 23.323 ;
     RECT  4.356 23.323 186.192 23.453 ;
     RECT  2.307 23.279 3.618 23.557 ;
     RECT  4.356 23.453 10.098 23.557 ;
     RECT  0.576 23.131 1.17 23.999 ;
     RECT  188.784 23.165 188.802 24.088 ;
     RECT  2.307 23.557 10.098 24.221 ;
     RECT  188.784 24.088 188.838 24.367 ;
     RECT  1.152 23.999 1.17 24.379 ;
     RECT  2.307 24.221 10.026 24.403 ;
     RECT  188.784 24.367 188.874 24.469 ;
     RECT  1.152 24.379 1.422 24.763 ;
     RECT  2.268 24.403 10.026 24.763 ;
     RECT  10.836 23.453 186.192 24.763 ;
     RECT  10.8 24.763 186.192 24.899 ;
     RECT  188.676 24.469 188.874 24.899 ;
     RECT  11.304 24.899 186.192 25.043 ;
     RECT  1.152 24.763 10.026 25.051 ;
     RECT  188.676 24.899 188.802 25.085 ;
     RECT  1.152 25.051 10.278 25.243 ;
     RECT  0.576 25.243 10.278 25.723 ;
     RECT  11.304 25.043 11.322 25.723 ;
     RECT  188.784 25.085 188.802 25.915 ;
     RECT  188.784 25.915 188.874 25.951 ;
     RECT  0.576 25.723 11.322 25.979 ;
     RECT  188.676 25.951 188.874 25.979 ;
     RECT  0.576 25.979 10.242 26.015 ;
     RECT  188.676 25.979 188.766 26.045 ;
     RECT  11.268 25.979 11.322 26.107 ;
     RECT  12.096 25.043 186.192 26.107 ;
     RECT  186.984 21.191 187.506 26.141 ;
     RECT  1.692 26.015 10.242 26.621 ;
     RECT  2.196 26.621 10.242 26.717 ;
     RECT  188.748 26.045 188.766 26.779 ;
     RECT  11.268 26.107 186.192 26.789 ;
     RECT  0.576 26.015 0.594 26.825 ;
     RECT  188.748 26.779 188.982 26.825 ;
     RECT  186.984 26.141 187.002 27.103 ;
     RECT  188.748 26.825 188.91 27.103 ;
     RECT  186.984 27.103 187.47 27.175 ;
     RECT  0.108 27.337 0.126 27.389 ;
     RECT  2.196 26.717 10.206 27.547 ;
     RECT  11.304 26.789 186.192 27.547 ;
     RECT  2.196 27.547 186.192 27.599 ;
     RECT  188.64 27.103 188.91 27.599 ;
     RECT  2.196 27.599 10.026 27.635 ;
     RECT  10.8 27.599 186.192 27.671 ;
     RECT  188.64 27.599 188.838 27.913 ;
     RECT  188.46 27.913 188.838 28.049 ;
     RECT  2.307 27.635 10.026 28.061 ;
     RECT  188.748 28.049 188.838 28.283 ;
     RECT  10.8 27.671 10.854 28.408 ;
     RECT  11.988 27.671 186.192 28.408 ;
     RECT  1.152 27.931 1.17 28.445 ;
     RECT  188.784 28.283 188.838 28.603 ;
     RECT  188.784 28.603 188.982 28.679 ;
     RECT  188.784 28.679 188.802 28.733 ;
     RECT  2.307 28.061 9.81 28.795 ;
     RECT  2.268 28.795 9.81 28.957 ;
     RECT  2.196 28.957 9.81 29.255 ;
     RECT  10.8 28.408 186.192 29.275 ;
     RECT  2.304 29.255 9.81 29.489 ;
     RECT  1.152 29.371 1.17 29.525 ;
     RECT  188.748 29.371 188.766 29.525 ;
     RECT  10.764 29.275 186.192 29.561 ;
     RECT  4.824 29.489 9.81 29.795 ;
     RECT  186.984 27.175 187.506 30.043 ;
     RECT  186.984 30.043 187.542 30.139 ;
     RECT  4.824 29.795 9.486 30.209 ;
     RECT  186.984 30.139 187.578 30.371 ;
     RECT  186.984 30.371 187.002 30.605 ;
     RECT  4.86 30.209 9.486 30.649 ;
     RECT  11.196 29.561 186.192 30.749 ;
     RECT  2.304 29.489 4.086 30.811 ;
     RECT  11.304 30.749 186.192 30.839 ;
     RECT  2.196 30.811 4.086 30.847 ;
     RECT  4.86 30.649 9.666 30.848 ;
     RECT  1.764 30.847 4.086 30.955 ;
     RECT  4.86 30.848 8.046 30.955 ;
     RECT  1.764 30.955 8.046 31.003 ;
     RECT  8.928 30.848 9.666 31.109 ;
     RECT  1.728 31.003 8.046 31.145 ;
     RECT  9.54 31.109 9.558 31.145 ;
     RECT  11.376 30.839 186.192 31.145 ;
     RECT  1.728 31.145 7.989 31.379 ;
     RECT  0.576 30.043 0.594 31.415 ;
     RECT  4.14 31.379 6.786 31.559 ;
     RECT  4.14 31.559 6.354 31.649 ;
     RECT  1.728 31.379 3.222 31.793 ;
     RECT  1.728 31.793 2.934 31.829 ;
     RECT  4.68 31.649 5.346 31.829 ;
     RECT  4.68 31.829 5.274 31.919 ;
     RECT  6.336 31.649 6.354 31.919 ;
     RECT  5.256 31.919 5.274 31.955 ;
     RECT  1.728 31.829 2.898 32.189 ;
     RECT  1.728 32.189 2.589 32.225 ;
     RECT  2.196 32.225 2.589 32.765 ;
     RECT  12.096 31.145 186.192 38.34 ;
     RECT  13.107 40.483 13.197 40.753 ;
     RECT  18.507 40.483 18.597 40.753 ;
     RECT  23.907 40.483 23.997 40.753 ;
     RECT  29.307 40.483 29.397 40.753 ;
     RECT  34.707 40.483 34.797 40.753 ;
     RECT  40.107 40.483 40.197 40.753 ;
     RECT  45.507 40.483 45.597 40.753 ;
     RECT  50.907 40.483 50.997 40.753 ;
     RECT  56.307 40.483 56.397 40.753 ;
     RECT  61.707 40.483 61.797 40.753 ;
     RECT  67.107 40.483 67.197 40.753 ;
     RECT  72.507 40.483 72.597 40.753 ;
     RECT  77.907 40.483 77.997 40.753 ;
     RECT  83.307 40.483 83.397 40.753 ;
     RECT  88.707 40.483 88.797 40.753 ;
     RECT  94.107 40.483 94.197 40.753 ;
     RECT  99.507 40.483 99.597 40.753 ;
     RECT  104.907 40.483 104.997 40.753 ;
     RECT  110.307 40.483 110.397 40.753 ;
     RECT  115.707 40.483 115.797 40.753 ;
     RECT  121.107 40.483 121.197 40.753 ;
     RECT  126.507 40.483 126.597 40.753 ;
     RECT  131.907 40.483 131.997 40.753 ;
     RECT  137.307 40.483 137.397 40.753 ;
     RECT  142.707 40.483 142.797 40.753 ;
     RECT  148.107 40.483 148.197 40.753 ;
     RECT  153.507 40.483 153.597 40.753 ;
     RECT  158.907 40.483 158.997 40.753 ;
     RECT  164.307 40.483 164.397 40.753 ;
     RECT  169.707 40.483 169.797 40.753 ;
     RECT  175.107 40.483 175.197 40.753 ;
     RECT  180.507 40.483 180.597 40.753 ;
     RECT  185.907 40.483 185.997 40.753 ;
     RECT  2.307 32.765 2.589 52.667 ;
     RECT  7.707 31.379 7.989 52.667 ;
     RECT  13.107 40.753 13.389 52.667 ;
     RECT  18.507 40.753 18.789 52.667 ;
     RECT  23.907 40.753 24.189 52.667 ;
     RECT  29.307 40.753 29.589 52.667 ;
     RECT  34.707 40.753 34.989 52.667 ;
     RECT  40.107 40.753 40.389 52.667 ;
     RECT  45.507 40.753 45.789 52.667 ;
     RECT  50.907 40.753 51.189 52.667 ;
     RECT  56.307 40.753 56.589 52.667 ;
     RECT  61.707 40.753 61.989 52.667 ;
     RECT  67.107 40.753 67.389 52.667 ;
     RECT  72.507 40.753 72.789 52.667 ;
     RECT  77.907 40.753 78.189 52.667 ;
     RECT  83.307 40.753 83.589 52.667 ;
     RECT  88.707 40.753 88.989 52.667 ;
     RECT  94.107 40.753 94.389 52.667 ;
     RECT  99.507 40.753 99.789 52.667 ;
     RECT  104.907 40.753 105.189 52.667 ;
     RECT  110.307 40.753 110.589 52.667 ;
     RECT  115.707 40.753 115.989 52.667 ;
     RECT  121.107 40.753 121.389 52.667 ;
     RECT  126.507 40.753 126.789 52.667 ;
     RECT  131.907 40.753 132.189 52.667 ;
     RECT  137.307 40.753 137.589 52.667 ;
     RECT  142.707 40.753 142.989 52.667 ;
     RECT  148.107 40.753 148.389 52.667 ;
     RECT  153.507 40.753 153.789 52.667 ;
     RECT  158.907 40.753 159.189 52.667 ;
     RECT  164.307 40.753 164.589 52.667 ;
     RECT  169.707 40.753 169.989 52.667 ;
     RECT  175.107 40.753 175.389 52.667 ;
     RECT  180.507 40.753 180.789 52.667 ;
     RECT  185.907 40.753 186.189 52.667 ;
     RECT  191.307 2.413 191.589 52.667 ;
     RECT  196.707 2.413 196.989 52.667 ;
     RECT  2.307 52.667 2.397 52.937 ;
     RECT  7.707 52.667 7.797 52.937 ;
     RECT  13.107 52.667 13.197 52.937 ;
     RECT  18.507 52.667 18.597 52.937 ;
     RECT  23.907 52.667 23.997 52.937 ;
     RECT  29.307 52.667 29.397 52.937 ;
     RECT  34.707 52.667 34.797 52.937 ;
     RECT  40.107 52.667 40.197 52.937 ;
     RECT  45.507 52.667 45.597 52.937 ;
     RECT  50.907 52.667 50.997 52.937 ;
     RECT  56.307 52.667 56.397 52.937 ;
     RECT  61.707 52.667 61.797 52.937 ;
     RECT  67.107 52.667 67.197 52.937 ;
     RECT  72.507 52.667 72.597 52.937 ;
     RECT  77.907 52.667 77.997 52.937 ;
     RECT  83.307 52.667 83.397 52.937 ;
     RECT  88.707 52.667 88.797 52.937 ;
     RECT  94.107 52.667 94.197 52.937 ;
     RECT  99.507 52.667 99.597 52.937 ;
     RECT  104.907 52.667 104.997 52.937 ;
     RECT  110.307 52.667 110.397 52.937 ;
     RECT  115.707 52.667 115.797 52.937 ;
     RECT  121.107 52.667 121.197 52.937 ;
     RECT  126.507 52.667 126.597 52.937 ;
     RECT  131.907 52.667 131.997 52.937 ;
     RECT  137.307 52.667 137.397 52.937 ;
     RECT  142.707 52.667 142.797 52.937 ;
     RECT  148.107 52.667 148.197 52.937 ;
     RECT  153.507 52.667 153.597 52.937 ;
     RECT  158.907 52.667 158.997 52.937 ;
     RECT  164.307 52.667 164.397 52.937 ;
     RECT  169.707 52.667 169.797 52.937 ;
     RECT  175.107 52.667 175.197 52.937 ;
     RECT  180.507 52.667 180.597 52.937 ;
     RECT  185.907 52.667 185.997 52.937 ;
     RECT  191.307 52.667 191.397 52.937 ;
     RECT  196.707 52.667 196.797 52.937 ;
    LAYER M4 ;
     RECT  0.06 19.392 0.131 31.032 ;
     RECT  0.06 11.52 0.137 11.544 ;
     RECT  0.06 12.768 0.137 12.792 ;
     RECT  0.131 19.392 0.137 28.344 ;
     RECT  0.131 29.376 0.605 31.032 ;
     RECT  0.06 3.264 1.181 4.44 ;
     RECT  0.137 19.392 1.181 26.616 ;
     RECT  0.137 27.936 1.181 28.344 ;
     RECT  0.605 29.376 1.181 29.4 ;
     RECT  0.605 30.816 1.909 31.032 ;
     RECT  1.909 30.336 2.149 31.032 ;
     RECT  1.717 32.544 2.149 32.568 ;
     RECT  2.257 5.76 2.3 5.784 ;
     RECT  2.257 8.496 2.3 8.52 ;
     RECT  2.257 12.048 2.3 12.072 ;
     RECT  2.257 15.456 2.3 15.48 ;
     RECT  2.149 16.512 2.3 16.536 ;
     RECT  1.717 17.616 2.3 17.64 ;
     RECT  1.181 19.392 2.3 20.952 ;
     RECT  1.181 22.272 2.3 22.296 ;
     RECT  1.181 24.384 2.3 24.792 ;
     RECT  1.181 26.4 2.3 26.616 ;
     RECT  1.717 28.992 2.3 29.112 ;
     RECT  2.149 30.336 2.3 32.568 ;
     RECT  2.3 2.148 2.404 52.932 ;
     RECT  2.404 2.418 2.596 52.662 ;
     RECT  2.596 13.152 2.657 13.176 ;
     RECT  2.596 26.064 2.723 26.088 ;
     RECT  2.596 29.664 2.801 31.368 ;
     RECT  2.801 29.76 2.867 31.368 ;
     RECT  2.596 22.704 2.909 24.216 ;
     RECT  2.596 27.792 2.956 27.816 ;
     RECT  2.867 30.672 3.011 31.368 ;
     RECT  2.596 18.768 3.017 21.096 ;
     RECT  2.596 14.544 3.197 15.48 ;
     RECT  3.011 30.864 3.233 31.368 ;
     RECT  3.017 20.256 3.305 21.096 ;
     RECT  2.596 7.68 3.341 9.864 ;
     RECT  2.909 22.704 3.341 23.976 ;
     RECT  3.305 20.256 3.347 20.28 ;
     RECT  2.596 11.424 3.377 12.072 ;
     RECT  3.377 11.424 3.443 11.448 ;
     RECT  2.596 5.76 3.449 5.784 ;
     RECT  3.233 30.864 3.449 30.888 ;
     RECT  3.341 7.872 3.521 9.864 ;
     RECT  3.521 7.872 3.629 8.52 ;
     RECT  3.197 14.544 3.697 14.904 ;
     RECT  3.017 18.768 3.733 19.08 ;
     RECT  3.341 23.568 3.772 23.976 ;
     RECT  3.521 9.6 3.841 9.864 ;
     RECT  3.625 6.048 3.913 6.072 ;
     RECT  3.913 6.048 3.949 6.264 ;
     RECT  3.697 14.208 3.949 14.904 ;
     RECT  3.733 18.192 4.129 19.08 ;
     RECT  4.213 16.416 4.273 16.44 ;
     RECT  4.129 17.568 4.273 19.08 ;
     RECT  3.949 13.968 4.345 14.904 ;
     RECT  4.273 16.416 4.457 19.08 ;
     RECT  3.769 3.552 4.493 3.576 ;
     RECT  4.345 13.968 4.517 15 ;
     RECT  4.457 16.416 4.517 16.824 ;
     RECT  3.949 6.048 4.525 6.888 ;
     RECT  4.457 18.096 4.547 19.08 ;
     RECT  4.517 13.968 4.565 16.824 ;
     RECT  4.547 19.056 4.565 19.08 ;
     RECT  4.525 5.904 4.597 6.888 ;
     RECT  3.629 7.872 4.597 7.896 ;
     RECT  3.841 9.6 4.597 9.912 ;
     RECT  4.565 13.968 4.601 16.296 ;
     RECT  4.597 9.6 4.709 10.824 ;
     RECT  4.597 5.904 4.741 7.896 ;
     RECT  4.601 13.968 4.741 15 ;
     RECT  4.741 5.28 4.957 7.896 ;
     RECT  4.957 4.32 5.065 7.896 ;
     RECT  4.709 9.6 5.065 9.864 ;
     RECT  4.705 19.248 5.123 19.992 ;
     RECT  4.525 31.248 5.137 31.272 ;
     RECT  5.123 19.248 5.141 19.512 ;
     RECT  5.245 23.52 5.329 23.544 ;
     RECT  3.877 24.528 5.42 24.552 ;
     RECT  4.309 2.304 5.425 2.328 ;
     RECT  5.42 24.288 5.507 24.552 ;
     RECT  5.245 26.256 5.569 26.28 ;
     RECT  5.425 2.208 5.605 2.328 ;
     RECT  5.605 2.208 5.653 2.712 ;
     RECT  5.137 31.248 5.699 31.416 ;
     RECT  5.653 2.112 5.701 2.712 ;
     RECT  5.065 4.32 5.701 9.864 ;
     RECT  5.701 2.112 5.753 9.864 ;
     RECT  5.507 24.528 5.753 24.552 ;
     RECT  5.753 2.688 5.788 3.528 ;
     RECT  5.569 26.256 5.804 26.52 ;
     RECT  5.804 26.256 5.891 26.76 ;
     RECT  5.753 4.944 5.897 9.864 ;
     RECT  5.891 26.256 6.005 26.28 ;
     RECT  5.713 11.568 6.14 11.592 ;
     RECT  5.141 19.488 6.181 19.512 ;
     RECT  6.14 11.568 6.253 11.688 ;
     RECT  6.181 19.488 6.277 19.656 ;
     RECT  5.821 18.192 6.293 18.216 ;
     RECT  6.277 19.488 6.293 19.944 ;
     RECT  5.897 7.872 6.325 9.864 ;
     RECT  6.253 10.896 6.325 11.688 ;
     RECT  4.741 13.632 6.325 15 ;
     RECT  5.897 4.944 6.329 6.648 ;
     RECT  6.325 7.872 6.373 11.688 ;
     RECT  4.601 16.272 6.421 16.296 ;
     RECT  6.373 7.872 6.46 12.216 ;
     RECT  6.421 15.984 6.508 16.488 ;
     RECT  6.517 0.576 6.617 0.6 ;
     RECT  6.325 13.536 6.721 15 ;
     RECT  6.721 13.392 6.829 15 ;
     RECT  6.508 15.984 6.829 16.296 ;
     RECT  6.649 22.752 6.829 22.776 ;
     RECT  6.829 22.56 6.853 22.776 ;
     RECT  6.505 24.048 6.853 24.072 ;
     RECT  6.433 25.152 6.865 25.176 ;
     RECT  5.788 2.688 6.973 2.712 ;
     RECT  6.829 13.392 7.045 16.296 ;
     RECT  6.865 25.152 7.045 25.512 ;
     RECT  6.901 0.096 7.193 0.12 ;
     RECT  6.329 4.944 7.333 6.024 ;
     RECT  6.46 7.872 7.441 11.592 ;
     RECT  7.045 13.104 7.441 16.296 ;
     RECT  6.901 27.6 7.573 27.624 ;
     RECT  7.045 25.152 7.621 26.232 ;
     RECT  7.573 27.6 7.621 27.912 ;
     RECT  6.293 19.632 7.693 19.944 ;
     RECT  6.973 2.688 7.7 3.432 ;
     RECT  7.333 4.704 7.7 6.024 ;
     RECT  7.441 7.872 7.7 16.296 ;
     RECT  7.693 19.632 7.7 20.616 ;
     RECT  6.853 22.56 7.7 24.072 ;
     RECT  7.621 25.152 7.7 27.912 ;
     RECT  6.997 29.424 7.7 29.448 ;
     RECT  6.997 30.816 7.7 30.84 ;
     RECT  7.7 2.148 7.804 52.932 ;
     RECT  7.804 2.418 7.996 52.662 ;
     RECT  7.996 27.072 8.165 27.624 ;
     RECT  7.996 2.832 8.273 3.432 ;
     RECT  7.996 22.56 8.291 23.544 ;
     RECT  7.996 24.864 8.291 25.704 ;
     RECT  7.996 30.816 8.291 30.84 ;
     RECT  7.996 12.48 8.381 16.056 ;
     RECT  8.291 22.56 8.381 23.304 ;
     RECT  7.996 19.344 8.417 20.616 ;
     RECT  8.417 19.344 8.425 20.04 ;
     RECT  8.425 20.016 8.428 20.04 ;
     RECT  7.957 0.576 8.449 0.6 ;
     RECT  8.449 0.576 8.485 0.648 ;
     RECT  8.381 22.608 8.531 23.304 ;
     RECT  7.996 17.088 8.579 17.688 ;
     RECT  8.485 0.096 8.771 0.648 ;
     RECT  8.771 0.576 8.773 0.648 ;
     RECT  7.996 7.728 8.777 7.896 ;
     RECT  8.773 0.576 8.921 1.176 ;
     RECT  8.777 7.872 8.993 7.896 ;
     RECT  8.273 2.832 9.013 3.24 ;
     RECT  7.996 9.504 9.025 11.4 ;
     RECT  9.025 9.504 9.061 11.448 ;
     RECT  8.381 12.48 9.061 15.24 ;
     RECT  8.291 25.056 9.061 25.704 ;
     RECT  8.165 27.312 9.061 27.624 ;
     RECT  9.061 27.312 9.097 28.344 ;
     RECT  9.097 27.312 9.205 28.824 ;
     RECT  9.205 27.312 9.241 29.112 ;
     RECT  9.061 25.056 9.253 25.8 ;
     RECT  9.241 27.072 9.253 29.112 ;
     RECT  7.996 4.704 9.277 6.024 ;
     RECT  9.013 2.352 9.281 3.24 ;
     RECT  9.281 2.352 9.347 2.904 ;
     RECT  9.253 25.056 9.457 29.112 ;
     RECT  8.921 1.152 9.46 1.176 ;
     RECT  9.46 1.152 9.461 1.224 ;
     RECT  9.461 1.2 9.569 1.224 ;
     RECT  8.531 22.752 9.637 23.304 ;
     RECT  9.457 24.672 9.637 29.112 ;
     RECT  9.061 9.504 9.673 15.24 ;
     RECT  9.347 2.352 9.685 2.376 ;
     RECT  9.673 9.504 9.757 16.056 ;
     RECT  9.877 18.192 9.964 18.216 ;
     RECT  9.685 2.304 10.109 2.376 ;
     RECT  9.277 4.512 10.285 6.024 ;
     RECT  10.285 3.888 10.393 6.024 ;
     RECT  10.109 2.304 10.613 2.328 ;
     RECT  10.393 3.408 10.717 6.024 ;
     RECT  9.637 22.752 10.753 29.112 ;
     RECT  10.717 3.408 10.787 6.168 ;
     RECT  10.787 4.656 10.801 6.168 ;
     RECT  10.753 22.752 10.825 29.304 ;
     RECT  10.801 4.656 10.865 6.024 ;
     RECT  10.825 22.752 11.185 29.4 ;
     RECT  11.185 22.752 11.293 30.264 ;
     RECT  10.787 3.408 11.729 3.432 ;
     RECT  9.757 9.504 11.845 15.576 ;
     RECT  11.293 22.752 11.941 30.36 ;
     RECT  11.845 9.504 11.989 15.672 ;
     RECT  10.709 1.152 12.053 1.176 ;
     RECT  10.865 4.704 12.085 6.024 ;
     RECT  11.989 9.408 12.096 15.672 ;
     RECT  9.385 21.408 12.096 21.432 ;
     RECT  11.941 22.704 12.096 30.36 ;
     RECT  12.096 9.408 12.168 30.36 ;
     RECT  12.085 3.84 12.181 6.024 ;
     RECT  12.181 3.84 12.229 6.12 ;
     RECT  12.229 3.84 12.757 6.888 ;
     RECT  12.168 8.64 12.757 38.34 ;
     RECT  12.481 2.736 12.853 2.856 ;
     RECT  12.853 2.304 13.1 2.856 ;
     RECT  12.757 3.84 13.1 38.34 ;
     RECT  13.1 2.148 13.204 38.34 ;
     RECT  13.1 40.488 13.204 52.932 ;
     RECT  13.204 2.304 13.396 38.34 ;
     RECT  13.204 40.758 13.396 52.662 ;
     RECT  13.141 0.096 13.565 0.12 ;
     RECT  13.396 2.304 13.565 2.52 ;
     RECT  13.396 4.272 13.667 38.34 ;
     RECT  13.667 4.368 14.677 38.34 ;
     RECT  13.565 2.496 15.077 2.52 ;
     RECT  14.677 4.08 15.397 38.34 ;
     RECT  15.397 3.936 15.685 38.34 ;
     RECT  15.685 3.408 15.725 38.34 ;
     RECT  15.725 3.408 16.069 3.432 ;
     RECT  13.805 1.152 16.085 1.176 ;
     RECT  16.069 2.64 16.115 3.432 ;
     RECT  15.725 4.512 16.307 38.34 ;
     RECT  16.307 4.752 16.337 38.34 ;
     RECT  16.115 2.64 16.501 2.664 ;
     RECT  16.337 4.752 16.625 6.12 ;
     RECT  16.625 5.04 17.018 6.12 ;
     RECT  17.153 1.152 17.237 1.176 ;
     RECT  16.501 2.304 17.417 2.664 ;
     RECT  17.018 5.04 17.593 6.072 ;
     RECT  17.417 2.304 18.5 2.328 ;
     RECT  17.593 4.416 18.5 6.072 ;
     RECT  16.337 7.104 18.5 38.34 ;
     RECT  18.5 2.148 18.604 38.34 ;
     RECT  18.5 40.488 18.604 52.932 ;
     RECT  18.229 0.576 18.677 0.6 ;
     RECT  18.604 2.304 18.796 38.34 ;
     RECT  18.604 40.758 18.796 52.662 ;
     RECT  18.881 1.152 18.965 1.176 ;
     RECT  18.796 4.416 19.037 6.072 ;
     RECT  18.796 2.304 19.073 3.432 ;
     RECT  19.073 2.448 19.145 3.432 ;
     RECT  19.037 4.416 19.469 5.496 ;
     RECT  19.145 2.448 19.981 3.336 ;
     RECT  18.796 7.104 20.081 38.34 ;
     RECT  20.053 0.192 20.141 0.216 ;
     RECT  20.141 0.192 20.225 1.176 ;
     RECT  19.981 2.448 20.245 2.664 ;
     RECT  19.469 5.232 20.261 5.496 ;
     RECT  20.225 0.192 20.341 0.216 ;
     RECT  20.245 2.304 21.109 2.664 ;
     RECT  21.109 2.304 21.197 2.856 ;
     RECT  20.977 4.416 21.212 4.44 ;
     RECT  21.212 3.936 21.299 4.44 ;
     RECT  21.299 4.416 21.701 4.44 ;
     RECT  20.341 0.096 21.737 0.216 ;
     RECT  20.261 5.472 22.205 5.496 ;
     RECT  21.197 2.448 22.561 2.856 ;
     RECT  21.737 0.144 22.637 0.216 ;
     RECT  20.081 7.104 22.637 7.128 ;
     RECT  22.637 0.144 22.709 0.168 ;
     RECT  22.561 2.448 23.9 3.048 ;
     RECT  22.705 4.656 23.9 5.16 ;
     RECT  23.9 2.148 24.004 6.492 ;
     RECT  23.9 40.488 24.004 52.932 ;
     RECT  24.004 2.418 24.196 6.222 ;
     RECT  24.004 40.758 24.196 52.662 ;
     RECT  29.3 2.148 29.404 6.492 ;
     RECT  29.3 40.488 29.404 52.932 ;
     RECT  29.404 2.418 29.596 6.222 ;
     RECT  29.404 40.758 29.596 52.662 ;
     RECT  34.7 2.148 34.804 6.492 ;
     RECT  34.7 40.488 34.804 52.932 ;
     RECT  34.804 2.418 34.996 6.222 ;
     RECT  34.804 40.758 34.996 52.662 ;
     RECT  40.1 2.148 40.204 6.492 ;
     RECT  40.1 40.488 40.204 52.932 ;
     RECT  40.204 2.418 40.396 6.222 ;
     RECT  40.204 40.758 40.396 52.662 ;
     RECT  45.5 2.148 45.604 6.492 ;
     RECT  45.5 40.488 45.604 52.932 ;
     RECT  45.604 2.418 45.796 6.222 ;
     RECT  45.604 40.758 45.796 52.662 ;
     RECT  50.9 2.148 51.004 6.492 ;
     RECT  50.9 40.488 51.004 52.932 ;
     RECT  51.004 2.418 51.196 6.222 ;
     RECT  51.004 40.758 51.196 52.662 ;
     RECT  56.3 2.148 56.404 6.492 ;
     RECT  56.3 40.488 56.404 52.932 ;
     RECT  56.404 2.418 56.596 6.222 ;
     RECT  56.404 40.758 56.596 52.662 ;
     RECT  61.7 2.148 61.804 6.492 ;
     RECT  61.7 40.488 61.804 52.932 ;
     RECT  61.804 2.418 61.996 6.222 ;
     RECT  61.804 40.758 61.996 52.662 ;
     RECT  67.1 2.148 67.204 6.492 ;
     RECT  67.1 40.488 67.204 52.932 ;
     RECT  67.204 2.418 67.396 6.222 ;
     RECT  67.204 40.758 67.396 52.662 ;
     RECT  72.5 2.148 72.604 6.492 ;
     RECT  72.5 40.488 72.604 52.932 ;
     RECT  72.604 2.418 72.796 6.222 ;
     RECT  72.604 40.758 72.796 52.662 ;
     RECT  77.9 2.148 78.004 6.492 ;
     RECT  77.9 40.488 78.004 52.932 ;
     RECT  78.004 2.418 78.196 6.222 ;
     RECT  78.004 40.758 78.196 52.662 ;
     RECT  83.3 2.148 83.404 6.492 ;
     RECT  83.3 40.488 83.404 52.932 ;
     RECT  83.404 2.418 83.596 6.222 ;
     RECT  83.404 40.758 83.596 52.662 ;
     RECT  88.7 2.148 88.804 6.492 ;
     RECT  88.7 40.488 88.804 52.932 ;
     RECT  88.804 2.418 88.996 6.222 ;
     RECT  88.804 40.758 88.996 52.662 ;
     RECT  94.1 2.148 94.204 6.492 ;
     RECT  94.1 40.488 94.204 52.932 ;
     RECT  94.204 2.418 94.396 6.222 ;
     RECT  94.204 40.758 94.396 52.662 ;
     RECT  99.5 2.148 99.604 6.492 ;
     RECT  99.5 40.488 99.604 52.932 ;
     RECT  99.604 2.418 99.796 6.222 ;
     RECT  99.604 40.758 99.796 52.662 ;
     RECT  104.9 2.148 105.004 6.492 ;
     RECT  104.9 40.488 105.004 52.932 ;
     RECT  105.004 2.418 105.196 6.222 ;
     RECT  105.004 40.758 105.196 52.662 ;
     RECT  110.3 2.148 110.404 6.492 ;
     RECT  110.3 40.488 110.404 52.932 ;
     RECT  110.404 2.418 110.596 6.222 ;
     RECT  110.404 40.758 110.596 52.662 ;
     RECT  115.7 2.148 115.804 6.492 ;
     RECT  115.7 40.488 115.804 52.932 ;
     RECT  115.804 2.418 115.996 6.222 ;
     RECT  115.804 40.758 115.996 52.662 ;
     RECT  121.1 2.148 121.204 6.492 ;
     RECT  121.1 40.488 121.204 52.932 ;
     RECT  121.204 2.418 121.396 6.222 ;
     RECT  121.204 40.758 121.396 52.662 ;
     RECT  126.5 2.148 126.604 6.492 ;
     RECT  126.5 40.488 126.604 52.932 ;
     RECT  126.604 2.418 126.796 6.222 ;
     RECT  126.604 40.758 126.796 52.662 ;
     RECT  131.9 2.148 132.004 6.492 ;
     RECT  131.9 40.488 132.004 52.932 ;
     RECT  132.004 2.418 132.196 6.222 ;
     RECT  132.004 40.758 132.196 52.662 ;
     RECT  137.3 2.148 137.404 6.492 ;
     RECT  137.3 40.488 137.404 52.932 ;
     RECT  137.404 2.418 137.596 6.222 ;
     RECT  137.404 40.758 137.596 52.662 ;
     RECT  142.7 2.148 142.804 6.492 ;
     RECT  142.7 40.488 142.804 52.932 ;
     RECT  142.804 2.418 142.996 6.222 ;
     RECT  142.804 40.758 142.996 52.662 ;
     RECT  148.1 2.148 148.204 6.492 ;
     RECT  148.1 40.488 148.204 52.932 ;
     RECT  148.204 2.418 148.396 6.222 ;
     RECT  148.204 40.758 148.396 52.662 ;
     RECT  153.5 2.148 153.604 6.492 ;
     RECT  153.5 40.488 153.604 52.932 ;
     RECT  153.604 2.418 153.796 6.222 ;
     RECT  153.604 40.758 153.796 52.662 ;
     RECT  158.9 2.148 159.004 6.492 ;
     RECT  158.9 40.488 159.004 52.932 ;
     RECT  159.004 2.418 159.196 6.222 ;
     RECT  159.004 40.758 159.196 52.662 ;
     RECT  164.3 2.148 164.404 6.492 ;
     RECT  164.3 40.488 164.404 52.932 ;
     RECT  164.404 2.418 164.596 6.222 ;
     RECT  164.404 40.758 164.596 52.662 ;
     RECT  169.7 2.148 169.804 6.492 ;
     RECT  169.7 40.488 169.804 52.932 ;
     RECT  169.804 2.418 169.996 6.222 ;
     RECT  169.804 40.758 169.996 52.662 ;
     RECT  175.1 2.148 175.204 6.492 ;
     RECT  175.1 40.488 175.204 52.932 ;
     RECT  175.204 2.418 175.396 6.222 ;
     RECT  175.204 40.758 175.396 52.662 ;
     RECT  180.5 2.148 180.604 6.492 ;
     RECT  180.5 40.488 180.604 52.932 ;
     RECT  180.604 2.418 180.796 6.222 ;
     RECT  180.604 40.758 180.796 52.662 ;
     RECT  185.9 2.148 186.004 6.492 ;
     RECT  185.9 40.488 186.004 52.932 ;
     RECT  20.081 8.64 186.12 38.34 ;
     RECT  186.004 2.418 186.196 6.222 ;
     RECT  186.004 40.758 186.196 52.662 ;
     RECT  186.12 9.408 187.013 30.264 ;
     RECT  187.013 9.408 187.517 30.168 ;
     RECT  187.517 10.752 187.589 30.168 ;
     RECT  187.517 9.408 188.453 9.528 ;
     RECT  188.453 9.408 188.669 9.432 ;
     RECT  187.589 10.752 188.777 29.4 ;
     RECT  188.777 10.752 188.813 10.872 ;
     RECT  188.777 11.904 188.813 13.56 ;
     RECT  188.777 14.976 188.813 28.728 ;
     RECT  188.813 24.096 188.849 24.888 ;
     RECT  188.813 25.92 188.849 28.632 ;
     RECT  188.813 14.976 188.885 22.968 ;
     RECT  188.849 24.384 188.885 24.888 ;
     RECT  188.849 25.92 188.885 27.576 ;
     RECT  188.885 22.656 188.921 22.68 ;
     RECT  188.885 26.784 188.921 27.576 ;
     RECT  188.813 12.672 188.957 12.696 ;
     RECT  188.813 10.848 188.993 10.872 ;
     RECT  188.885 14.976 188.993 16.152 ;
     RECT  188.885 18.72 188.993 18.744 ;
     RECT  188.885 21.312 188.993 21.336 ;
     RECT  188.921 26.784 188.993 26.808 ;
     RECT  188.849 28.608 188.993 28.632 ;
     RECT  188.885 17.472 189.029 17.688 ;
     RECT  188.993 14.976 189.101 15.192 ;
     RECT  189.029 17.472 189.101 17.496 ;
     RECT  189.101 14.976 189.209 15 ;
     RECT  191.3 2.148 191.404 52.932 ;
     RECT  191.404 2.418 191.596 52.662 ;
     RECT  196.7 2.148 196.804 52.932 ;
     RECT  196.804 2.418 196.996 52.662 ;
    LAYER M5 ;
     RECT  4.32 0.016 6.936 0.131 ;
     RECT  16.032 0.016 20.472 0.179 ;
     RECT  16.032 0.179 20.28 0.227 ;
     RECT  4.32 0.131 6.552 0.611 ;
     RECT  7.968 0.016 9.72 0.611 ;
     RECT  8.64 0.611 9.72 0.659 ;
     RECT  8.928 0.659 9.72 1.187 ;
     RECT  10.752 0.016 10.968 1.187 ;
     RECT  12 0.016 15 1.187 ;
     RECT  16.032 0.227 19.128 1.187 ;
     RECT  20.16 0.227 20.28 1.187 ;
     RECT  4.32 0.611 5.688 2.339 ;
     RECT  9.024 1.187 9.72 2.339 ;
     RECT  16.512 1.187 16.536 2.339 ;
     RECT  17.952 1.187 19.128 2.339 ;
     RECT  20.256 1.187 20.28 2.339 ;
     RECT  9.024 2.339 9.336 2.387 ;
     RECT  2.292 2.137 2.412 2.407 ;
     RECT  7.692 2.137 7.812 2.407 ;
     RECT  12.864 1.187 13.212 2.407 ;
     RECT  23.892 2.137 24.012 2.407 ;
     RECT  29.292 2.137 29.412 2.407 ;
     RECT  34.692 2.137 34.812 2.407 ;
     RECT  40.092 2.137 40.212 2.407 ;
     RECT  45.492 2.137 45.612 2.407 ;
     RECT  50.892 2.137 51.012 2.407 ;
     RECT  56.292 2.137 56.412 2.407 ;
     RECT  61.692 2.137 61.812 2.407 ;
     RECT  67.092 2.137 67.212 2.407 ;
     RECT  72.492 2.137 72.612 2.407 ;
     RECT  77.892 2.137 78.012 2.407 ;
     RECT  83.292 2.137 83.412 2.407 ;
     RECT  88.692 2.137 88.812 2.407 ;
     RECT  94.092 2.137 94.212 2.407 ;
     RECT  99.492 2.137 99.612 2.407 ;
     RECT  104.892 2.137 105.012 2.407 ;
     RECT  110.292 2.137 110.412 2.407 ;
     RECT  115.692 2.137 115.812 2.407 ;
     RECT  121.092 2.137 121.212 2.407 ;
     RECT  126.492 2.137 126.612 2.407 ;
     RECT  131.892 2.137 132.012 2.407 ;
     RECT  137.292 2.137 137.412 2.407 ;
     RECT  142.692 2.137 142.812 2.407 ;
     RECT  148.092 2.137 148.212 2.407 ;
     RECT  153.492 2.137 153.612 2.407 ;
     RECT  158.892 2.137 159.012 2.407 ;
     RECT  164.292 2.137 164.412 2.407 ;
     RECT  169.692 2.137 169.812 2.407 ;
     RECT  175.092 2.137 175.212 2.407 ;
     RECT  180.492 2.137 180.612 2.407 ;
     RECT  185.892 2.137 186.012 2.407 ;
     RECT  191.292 2.137 191.412 2.407 ;
     RECT  196.692 2.137 196.812 2.407 ;
     RECT  14.976 2.357 15 2.531 ;
     RECT  12.864 2.407 13.404 2.821 ;
     RECT  23.892 2.407 24.204 2.821 ;
     RECT  9.216 2.387 9.336 2.915 ;
     RECT  23.664 2.821 24.204 3.059 ;
     RECT  9.216 2.915 9.24 3.251 ;
     RECT  18.492 2.339 19.128 3.301 ;
     RECT  21.12 2.629 21.144 3.371 ;
     RECT  18.492 3.301 19.944 3.385 ;
     RECT  16.08 2.629 16.104 3.443 ;
     RECT  18.492 3.385 19.128 3.443 ;
     RECT  5.712 2.677 5.736 3.539 ;
     RECT  12.528 2.821 13.404 3.829 ;
     RECT  10.752 3.877 10.776 4.011 ;
     RECT  21.264 3.925 21.288 4.011 ;
     RECT  15.408 3.925 15.432 4.021 ;
     RECT  12.384 3.829 13.404 4.243 ;
     RECT  14.784 4.021 15.432 4.355 ;
     RECT  12.384 4.243 13.656 4.357 ;
     RECT  14.784 4.355 15.048 4.357 ;
     RECT  18.492 3.443 18.804 4.405 ;
     RECT  17.616 4.405 19.416 4.489 ;
     RECT  9.648 4.501 9.672 4.533 ;
     RECT  12.384 4.357 15.048 4.533 ;
     RECT  16.272 4.501 16.296 4.587 ;
     RECT  9.648 4.533 10.488 4.691 ;
     RECT  18.492 4.489 18.984 4.715 ;
     RECT  7.692 2.407 8.004 4.741 ;
     RECT  7.584 4.741 8.004 4.843 ;
     RECT  12.336 4.533 15.048 4.947 ;
     RECT  12.048 4.947 15.048 5.035 ;
     RECT  22.8 5.087 22.824 5.171 ;
     RECT  12.384 5.035 15.048 5.363 ;
     RECT  9.6 5.077 9.624 5.411 ;
     RECT  10.752 5.685 10.776 5.845 ;
     RECT  9.984 5.845 10.776 5.931 ;
     RECT  12.384 5.363 14.808 6.085 ;
     RECT  16.56 6.047 16.584 6.131 ;
     RECT  10.752 5.931 10.776 6.179 ;
     RECT  12.192 6.085 14.808 6.325 ;
     RECT  12.192 6.325 15.432 6.419 ;
     RECT  7.692 4.843 8.004 7.797 ;
     RECT  7.692 7.797 8.712 7.907 ;
     RECT  2.292 2.407 2.604 8.485 ;
     RECT  2.292 8.485 3.48 8.747 ;
     RECT  12.192 6.419 14.472 9.333 ;
     RECT  12 9.333 14.472 9.443 ;
     RECT  7.692 7.907 8.004 9.717 ;
     RECT  7.692 9.717 8.808 9.805 ;
     RECT  7.692 9.805 8.136 9.845 ;
     RECT  7.392 9.845 8.136 10.597 ;
     RECT  6.816 10.597 8.136 10.681 ;
     RECT  12.192 9.443 14.472 11.061 ;
     RECT  2.292 8.747 2.604 11.375 ;
     RECT  2.292 11.375 3.432 11.459 ;
     RECT  7.692 10.681 8.136 11.691 ;
     RECT  6.192 11.637 6.408 11.725 ;
     RECT  12 11.061 14.472 12.044 ;
     RECT  6.384 11.725 6.408 12.227 ;
     RECT  11.952 12.044 14.472 12.267 ;
     RECT  14.448 12.267 14.472 12.779 ;
     RECT  11.952 12.267 13.404 12.907 ;
     RECT  7.692 11.691 8.004 13.173 ;
     RECT  7.692 13.173 8.328 13.667 ;
     RECT  12 12.907 12.024 13.957 ;
     RECT  10.848 13.957 10.872 14.195 ;
     RECT  7.692 13.667 8.004 14.739 ;
     RECT  7.692 14.739 8.328 14.827 ;
     RECT  12 13.957 12.072 14.917 ;
     RECT  11.952 14.917 12.072 14.963 ;
     RECT  11.952 14.963 11.976 15.157 ;
     RECT  11.856 15.157 11.976 15.203 ;
     RECT  11.856 15.203 11.88 15.683 ;
     RECT  7.692 14.827 8.004 15.861 ;
     RECT  6.816 15.861 8.004 15.925 ;
     RECT  6.432 15.925 8.004 15.973 ;
     RECT  6.432 15.973 8.136 15.983 ;
     RECT  4.56 15.925 4.584 16.009 ;
     RECT  6.432 15.983 8.328 16.019 ;
     RECT  7.692 16.019 8.328 16.067 ;
     RECT  9.696 15.983 9.72 16.067 ;
     RECT  6.432 16.019 6.6 16.171 ;
     RECT  6.432 16.171 6.456 16.499 ;
     RECT  2.292 11.459 2.604 16.501 ;
     RECT  4.224 16.405 4.248 16.555 ;
     RECT  2.16 16.501 2.604 16.585 ;
     RECT  7.692 16.067 8.004 17.077 ;
     RECT  2.292 16.585 2.604 17.567 ;
     RECT  1.728 17.567 2.604 17.651 ;
     RECT  7.692 17.077 8.568 17.699 ;
     RECT  4.512 18.037 4.536 18.131 ;
     RECT  3.936 18.143 3.96 18.227 ;
     RECT  9.888 18.165 9.912 18.253 ;
     RECT  7.692 17.699 8.004 19.333 ;
     RECT  0.096 19.701 0.12 19.811 ;
     RECT  6.288 19.871 6.312 19.955 ;
     RECT  5.088 19.237 5.112 20.003 ;
     RECT  7.692 19.333 8.376 20.051 ;
     RECT  2.292 17.651 2.604 20.213 ;
     RECT  0.144 20.053 0.168 20.243 ;
     RECT  2.292 20.213 3.336 20.301 ;
     RECT  7.692 20.051 8.328 20.557 ;
     RECT  2.292 20.301 2.604 22.197 ;
     RECT  1.728 22.197 2.604 22.307 ;
     RECT  7.692 20.557 8.004 22.597 ;
     RECT  12 21.397 12.024 22.675 ;
     RECT  2.292 22.307 2.604 22.693 ;
     RECT  7.692 22.597 8.52 22.699 ;
     RECT  11.952 22.675 12.024 22.709 ;
     RECT  13.092 12.907 13.404 22.709 ;
     RECT  11.952 22.709 13.404 22.789 ;
     RECT  0.096 22.165 0.12 22.989 ;
     RECT  0.528 23.029 0.552 23.147 ;
     RECT  2.292 22.693 3 23.251 ;
     RECT  7.692 22.699 8.28 23.279 ;
     RECT  11.904 22.789 13.404 23.339 ;
     RECT  6.864 23.279 8.28 23.363 ;
     RECT  7.584 23.363 8.28 23.411 ;
     RECT  11.952 23.339 13.404 23.531 ;
     RECT  2.292 23.251 3.096 23.541 ;
     RECT  5.28 23.413 5.304 23.555 ;
     RECT  7.692 23.411 8.28 23.555 ;
     RECT  2.292 23.541 3.72 23.629 ;
     RECT  2.292 23.629 2.904 23.987 ;
     RECT  5.472 23.989 5.496 24.323 ;
     RECT  7.692 23.555 8.004 24.853 ;
     RECT  9.552 25.045 9.576 25.141 ;
     RECT  9.552 25.141 9.624 25.573 ;
     RECT  9.552 25.573 9.672 25.621 ;
     RECT  7.692 24.853 8.28 25.653 ;
     RECT  9.456 25.621 9.672 25.653 ;
     RECT  7.44 25.653 9.672 25.741 ;
     RECT  10.848 25.765 10.872 25.955 ;
     RECT  2.292 23.987 2.604 26.037 ;
     RECT  2.292 26.037 2.712 26.125 ;
     RECT  7.44 25.741 8.004 26.197 ;
     RECT  5.856 26.707 5.88 26.795 ;
     RECT  9.264 25.741 9.672 26.915 ;
     RECT  9.264 26.915 9.624 27.059 ;
     RECT  12 23.531 13.404 27.404 ;
     RECT  11.952 27.404 13.404 27.541 ;
     RECT  11.904 27.541 13.404 27.627 ;
     RECT  7.056 26.197 8.004 27.635 ;
     RECT  11.904 27.627 12.072 27.691 ;
     RECT  2.292 26.125 2.604 27.781 ;
     RECT  12 27.691 12.072 27.875 ;
     RECT  2.292 27.781 2.904 27.883 ;
     RECT  7.584 27.635 8.004 27.947 ;
     RECT  9.264 27.059 9.576 27.971 ;
     RECT  12 27.875 12.024 28.011 ;
     RECT  2.292 27.883 2.604 28.789 ;
     RECT  1.728 28.789 2.604 29.123 ;
     RECT  9.264 27.971 9.288 29.123 ;
     RECT  1.776 29.123 2.604 29.365 ;
     RECT  7.692 27.947 8.004 29.365 ;
     RECT  7.008 29.365 8.004 29.459 ;
     RECT  1.776 29.365 2.856 29.483 ;
     RECT  0.096 28.755 0.12 29.749 ;
     RECT  0.096 29.749 0.552 30.379 ;
     RECT  0.096 30.379 0.36 30.571 ;
     RECT  1.92 29.483 2.856 30.661 ;
     RECT  0.192 30.571 0.36 30.699 ;
     RECT  0.336 30.699 0.36 30.763 ;
     RECT  1.92 30.661 3 30.773 ;
     RECT  7.692 29.459 8.004 30.773 ;
     RECT  1.728 30.773 3 30.803 ;
     RECT  7.692 30.773 8.28 30.805 ;
     RECT  7.008 30.805 8.28 30.861 ;
     RECT  1.728 30.803 2.904 30.899 ;
     RECT  7.008 30.861 8.004 31.147 ;
     RECT  2.292 30.899 2.904 31.379 ;
     RECT  5.664 31.093 5.688 31.427 ;
     RECT  2.292 31.379 2.604 31.909 ;
     RECT  2.16 31.909 2.604 32.495 ;
     RECT  1.728 32.495 2.604 32.579 ;
     RECT  2.292 32.579 2.604 52.673 ;
     RECT  7.692 31.147 8.004 52.673 ;
     RECT  13.092 27.627 13.404 52.673 ;
     RECT  18.492 4.715 18.804 52.673 ;
     RECT  23.892 3.059 24.204 52.673 ;
     RECT  29.292 2.407 29.604 52.673 ;
     RECT  34.692 2.407 35.004 52.673 ;
     RECT  40.092 2.407 40.404 52.673 ;
     RECT  45.492 2.407 45.804 52.673 ;
     RECT  50.892 2.407 51.204 52.673 ;
     RECT  56.292 2.407 56.604 52.673 ;
     RECT  61.692 2.407 62.004 52.673 ;
     RECT  67.092 2.407 67.404 52.673 ;
     RECT  72.492 2.407 72.804 52.673 ;
     RECT  77.892 2.407 78.204 52.673 ;
     RECT  83.292 2.407 83.604 52.673 ;
     RECT  88.692 2.407 89.004 52.673 ;
     RECT  94.092 2.407 94.404 52.673 ;
     RECT  99.492 2.407 99.804 52.673 ;
     RECT  104.892 2.407 105.204 52.673 ;
     RECT  110.292 2.407 110.604 52.673 ;
     RECT  115.692 2.407 116.004 52.673 ;
     RECT  121.092 2.407 121.404 52.673 ;
     RECT  126.492 2.407 126.804 52.673 ;
     RECT  131.892 2.407 132.204 52.673 ;
     RECT  137.292 2.407 137.604 52.673 ;
     RECT  142.692 2.407 143.004 52.673 ;
     RECT  148.092 2.407 148.404 52.673 ;
     RECT  153.492 2.407 153.804 52.673 ;
     RECT  158.892 2.407 159.204 52.673 ;
     RECT  164.292 2.407 164.604 52.673 ;
     RECT  169.692 2.407 170.004 52.673 ;
     RECT  175.092 2.407 175.404 52.673 ;
     RECT  180.492 2.407 180.804 52.673 ;
     RECT  185.892 2.407 186.204 52.673 ;
     RECT  191.292 2.407 191.604 52.673 ;
     RECT  196.692 2.407 197.004 52.673 ;
     RECT  2.292 52.673 2.412 52.943 ;
     RECT  7.692 52.673 7.812 52.943 ;
     RECT  13.092 52.673 13.212 52.943 ;
     RECT  18.492 52.673 18.612 52.943 ;
     RECT  23.892 52.673 24.012 52.943 ;
     RECT  29.292 52.673 29.412 52.943 ;
     RECT  34.692 52.673 34.812 52.943 ;
     RECT  40.092 52.673 40.212 52.943 ;
     RECT  45.492 52.673 45.612 52.943 ;
     RECT  50.892 52.673 51.012 52.943 ;
     RECT  56.292 52.673 56.412 52.943 ;
     RECT  61.692 52.673 61.812 52.943 ;
     RECT  67.092 52.673 67.212 52.943 ;
     RECT  72.492 52.673 72.612 52.943 ;
     RECT  77.892 52.673 78.012 52.943 ;
     RECT  83.292 52.673 83.412 52.943 ;
     RECT  88.692 52.673 88.812 52.943 ;
     RECT  94.092 52.673 94.212 52.943 ;
     RECT  99.492 52.673 99.612 52.943 ;
     RECT  104.892 52.673 105.012 52.943 ;
     RECT  110.292 52.673 110.412 52.943 ;
     RECT  115.692 52.673 115.812 52.943 ;
     RECT  121.092 52.673 121.212 52.943 ;
     RECT  126.492 52.673 126.612 52.943 ;
     RECT  131.892 52.673 132.012 52.943 ;
     RECT  137.292 52.673 137.412 52.943 ;
     RECT  142.692 52.673 142.812 52.943 ;
     RECT  148.092 52.673 148.212 52.943 ;
     RECT  153.492 52.673 153.612 52.943 ;
     RECT  158.892 52.673 159.012 52.943 ;
     RECT  164.292 52.673 164.412 52.943 ;
     RECT  169.692 52.673 169.812 52.943 ;
     RECT  175.092 52.673 175.212 52.943 ;
     RECT  180.492 52.673 180.612 52.943 ;
     RECT  185.892 52.673 186.012 52.943 ;
     RECT  191.292 52.673 191.412 52.943 ;
     RECT  196.692 52.673 196.812 52.943 ;
    LAYER M6 ;
     RECT  0.053 23.552 0.085 23.584 ;
     RECT  0.053 30.528 0.085 30.56 ;
     RECT  0.085 28.8 0.162 30.56 ;
     RECT  0.085 19.712 0.171 19.744 ;
     RECT  0.162 28.8 0.309 30.688 ;
     RECT  0.181 32.512 0.309 32.544 ;
     RECT  0.117 17.6 1.763 17.632 ;
     RECT  0.085 22.208 1.763 23.584 ;
     RECT  0.309 28.8 1.763 32.544 ;
     RECT  1.763 22.784 2.052 23.584 ;
     RECT  1.763 29.376 2.195 30.368 ;
     RECT  1.763 31.936 2.195 31.968 ;
     RECT  2.052 22.784 2.658 24.801 ;
     RECT  2.658 22.784 2.731 26.08 ;
     RECT  2.195 29.376 2.867 30.201 ;
     RECT  2.805 27.84 2.915 27.872 ;
     RECT  2.731 22.784 3.011 24.801 ;
     RECT  2.052 18.729 3.301 19.401 ;
     RECT  2.052 7.929 3.445 8.601 ;
     RECT  3.397 11.392 3.445 11.424 ;
     RECT  3.445 10.432 3.499 11.424 ;
     RECT  3.445 7.929 3.514 8.736 ;
     RECT  3.301 18.729 3.925 20.256 ;
     RECT  2.149 16.512 4.259 16.544 ;
     RECT  3.925 18.176 4.501 20.256 ;
     RECT  4.501 18.048 4.587 20.256 ;
     RECT  2.052 2.529 5.653 3.201 ;
     RECT  2.867 29.529 5.653 30.201 ;
     RECT  3.499 10.432 6.181 10.464 ;
     RECT  4.587 18.176 6.323 19.936 ;
     RECT  4.526 15.936 6.611 16.16 ;
     RECT  6.611 15.936 6.805 16.032 ;
     RECT  5.845 26.752 6.965 26.784 ;
     RECT  5.653 29.529 6.965 31.392 ;
     RECT  6.965 29.376 7.019 31.392 ;
     RECT  7.019 29.376 7.043 31.136 ;
     RECT  6.965 26.752 7.091 27.936 ;
     RECT  3.514 7.929 7.381 8.601 ;
     RECT  6.181 10.432 7.381 11.68 ;
     RECT  3.011 23.296 7.413 24.801 ;
     RECT  7.091 27.904 7.619 27.936 ;
     RECT  5.653 2.24 7.979 3.201 ;
     RECT  7.573 4.8 7.979 4.832 ;
     RECT  2.052 13.329 8.053 14.001 ;
     RECT  7.381 7.929 8.147 11.68 ;
     RECT  8.147 7.929 8.149 10.784 ;
     RECT  8.053 13.184 8.245 14.001 ;
     RECT  6.805 15.872 8.245 16.032 ;
     RECT  6.323 18.176 8.245 19.401 ;
     RECT  8.245 17.6 8.314 20.512 ;
     RECT  7.043 29.529 8.314 30.816 ;
     RECT  8.245 13.184 8.339 16.032 ;
     RECT  8.314 18.176 8.339 20.512 ;
     RECT  8.339 18.176 8.387 20 ;
     RECT  8.387 18.176 8.427 19.552 ;
     RECT  7.413 23.296 8.427 25.696 ;
     RECT  8.485 22.656 8.555 22.688 ;
     RECT  8.427 24.129 8.579 25.696 ;
     RECT  8.149 7.929 8.677 9.888 ;
     RECT  7.669 6.208 8.693 6.24 ;
     RECT  8.677 7.808 8.747 9.888 ;
     RECT  8.693 5.888 8.821 6.24 ;
     RECT  8.747 7.929 8.875 9.76 ;
     RECT  9.637 4.544 9.717 4.576 ;
     RECT  8.821 5.888 9.717 6.368 ;
     RECT  9.685 16 9.771 16.032 ;
     RECT  8.427 18.176 9.923 19.401 ;
     RECT  7.979 2.529 10.741 3.201 ;
     RECT  9.717 4.544 10.741 6.368 ;
     RECT  8.579 24.129 11.893 24.801 ;
     RECT  8.339 13.329 11.941 14.001 ;
     RECT  11.893 23.296 11.941 24.801 ;
     RECT  11.893 27.648 11.941 27.68 ;
     RECT  8.875 7.929 11.989 8.601 ;
     RECT  11.941 12.096 11.989 14.001 ;
     RECT  11.941 27.456 11.989 27.68 ;
     RECT  10.741 2.529 12.083 6.368 ;
     RECT  11.989 7.929 12.139 9.376 ;
     RECT  11.989 27.328 12.203 28 ;
     RECT  11.941 22.72 12.227 24.801 ;
     RECT  12.203 27.328 12.227 27.616 ;
     RECT  11.989 11.072 12.419 14.001 ;
     RECT  12.227 23.168 12.563 24.801 ;
     RECT  12.227 27.456 12.563 27.616 ;
     RECT  12.563 23.616 12.611 24.801 ;
     RECT  12.563 27.456 12.611 27.488 ;
     RECT  12.419 11.648 12.995 14.001 ;
     RECT  12.805 10.24 13.523 10.272 ;
     RECT  12.995 11.84 13.715 14.001 ;
     RECT  12.083 2.529 13.955 4.704 ;
     RECT  13.715 12.224 13.955 14.001 ;
     RECT  13.955 12.736 14.483 14.001 ;
     RECT  13.955 2.529 14.965 4.576 ;
     RECT  14.965 2.368 15.147 4.576 ;
     RECT  15.147 2.529 15.443 4.576 ;
     RECT  12.083 6.08 15.443 6.368 ;
     RECT  15.443 6.08 16.595 6.112 ;
     RECT  15.443 2.529 17.605 3.201 ;
     RECT  15.443 4.544 17.605 4.576 ;
     RECT  17.605 2.529 18.949 4.576 ;
     RECT  18.949 2.529 19.427 4.704 ;
     RECT  19.427 2.529 21.253 3.36 ;
     RECT  19.427 4.672 21.253 4.704 ;
     RECT  21.253 2.529 21.301 4.704 ;
     RECT  21.301 2.529 21.355 5.152 ;
     RECT  21.355 5.12 22.835 5.152 ;
     RECT  21.355 2.529 197.964 3.201 ;
     RECT  12.139 7.929 197.964 8.601 ;
     RECT  14.483 13.329 197.964 14.001 ;
     RECT  9.923 18.729 197.964 19.401 ;
     RECT  12.611 24.129 197.964 24.801 ;
     RECT  8.314 29.529 197.964 30.201 ;
     RECT  2.052 34.929 197.964 35.601 ;
     RECT  2.052 40.329 197.964 41.001 ;
     RECT  2.052 45.729 197.964 46.401 ;
     RECT  2.052 51.129 197.964 51.801 ;
    LAYER M7 ;
     RECT  15.104 2.357 15.136 4.331 ;
     RECT  10.752 3.957 10.784 4.981 ;
     RECT  21.312 3.957 21.344 5.163 ;
     RECT  9.728 4.981 10.784 5.739 ;
     RECT  7.936 2.229 7.968 5.877 ;
     RECT  9.728 5.739 9.76 5.877 ;
     RECT  12.096 3.829 12.128 6.069 ;
     RECT  7.936 5.877 9.76 6.197 ;
     RECT  12.096 6.069 12.192 9.387 ;
     RECT  7.68 6.197 9.76 9.899 ;
     RECT  7.68 9.899 8.096 10.293 ;
     RECT  3.456 8.693 3.488 11.435 ;
     RECT  12.16 9.387 12.192 11.499 ;
     RECT  7.424 10.293 8.096 13.227 ;
     RECT  7.424 13.227 7.456 14.773 ;
     RECT  7.424 14.773 8.288 16.043 ;
     RECT  9.728 9.899 9.76 16.043 ;
     RECT  4.544 15.925 4.576 16.117 ;
     RECT  7.424 16.043 7.456 17.589 ;
     RECT  7.424 17.589 8.288 18.219 ;
     RECT  7.872 18.219 8.288 19.509 ;
     RECT  0.128 17.589 0.16 19.755 ;
     RECT  4.544 16.117 5.344 20.267 ;
     RECT  7.872 19.509 8.416 22.645 ;
     RECT  2.816 22.965 2.848 23.285 ;
     RECT  5.312 20.267 5.344 23.285 ;
     RECT  7.872 22.645 8.544 23.285 ;
     RECT  12.096 22.965 12.128 23.285 ;
     RECT  5.312 23.285 5.536 23.467 ;
     RECT  12.032 23.285 12.128 23.477 ;
     RECT  2.688 23.285 2.848 23.979 ;
     RECT  5.504 23.467 5.536 24.043 ;
     RECT  7.424 23.285 8.544 25.707 ;
     RECT  12.032 23.477 12.192 27.819 ;
     RECT  2.688 23.979 2.72 27.829 ;
     RECT  8.256 25.707 8.288 27.893 ;
     RECT  12.16 27.819 12.192 28.011 ;
     RECT  2.688 27.829 2.848 29.419 ;
     RECT  0.064 23.541 0.096 29.877 ;
     RECT  0.064 29.877 0.48 30.571 ;
     RECT  0.192 30.571 0.48 30.827 ;
     RECT  6.976 27.893 8.288 30.827 ;
     RECT  6.976 30.827 7.008 31.403 ;
     RECT  0.192 30.827 0.352 31.979 ;
     RECT  0.192 31.979 0.224 32.555 ;
  END
END ot_hdc_v41_fh_sram_lane_hardened
END LIBRARY
